VERSION 5.8 ;
BUSBITCHARS "[]" ;
DIVIDERCHAR "/" ;
UNITS
    DATABASE MICRONS 1000 ;
END UNITS

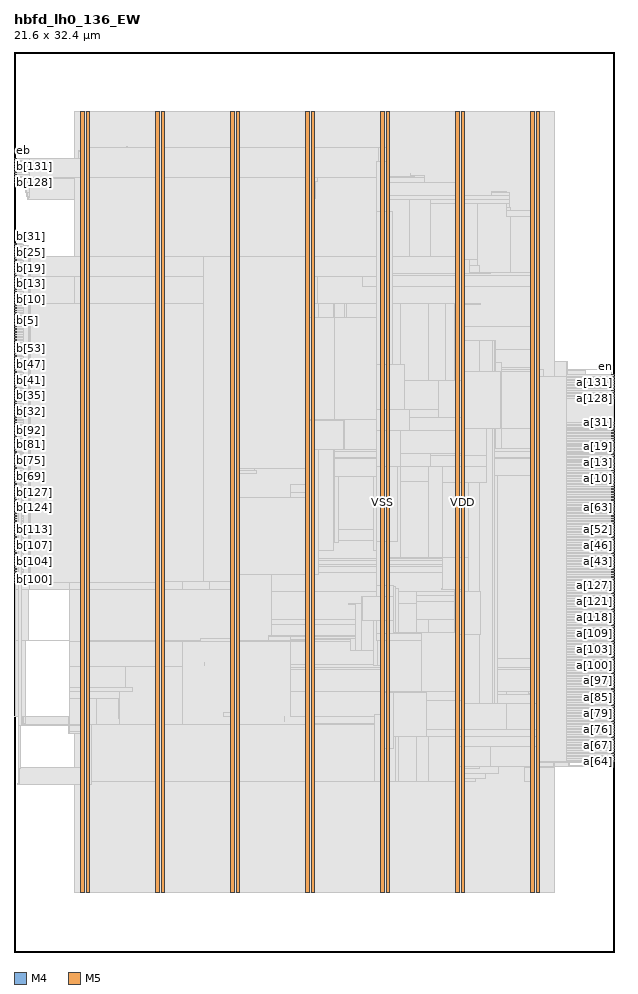
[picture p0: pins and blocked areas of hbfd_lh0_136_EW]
MACRO hbfd_lh0_136_EW
  FOREIGN hbfd_lh0_136_EW 0 0 ;
  CLASS BLOCK ;
  SIZE 21.6 BY 32.4 ;
  PIN a[0]
    DIRECTION INPUT ;
    USE SIGNAL ;
    PORT
      LAYER M4 ;
        RECT  21.516 16.08 21.6 16.104 ;
    END
  END a[0]
  PIN a[100]
    DIRECTION INPUT ;
    USE SIGNAL ;
    PORT
      LAYER M4 ;
        RECT  21.516 10.32 21.6 10.344 ;
    END
  END a[100]
  PIN a[101]
    DIRECTION INPUT ;
    USE SIGNAL ;
    PORT
      LAYER M4 ;
        RECT  21.516 10.416 21.6 10.44 ;
    END
  END a[101]
  PIN a[102]
    DIRECTION INPUT ;
    USE SIGNAL ;
    PORT
      LAYER M4 ;
        RECT  21.516 10.512 21.6 10.536 ;
    END
  END a[102]
  PIN a[103]
    DIRECTION INPUT ;
    USE SIGNAL ;
    PORT
      LAYER M4 ;
        RECT  21.516 10.608 21.6 10.632 ;
    END
  END a[103]
  PIN a[104]
    DIRECTION INPUT ;
    USE SIGNAL ;
    PORT
      LAYER M4 ;
        RECT  21.516 10.704 21.6 10.728 ;
    END
  END a[104]
  PIN a[105]
    DIRECTION INPUT ;
    USE SIGNAL ;
    PORT
      LAYER M4 ;
        RECT  21.516 10.8 21.6 10.824 ;
    END
  END a[105]
  PIN a[106]
    DIRECTION INPUT ;
    USE SIGNAL ;
    PORT
      LAYER M4 ;
        RECT  21.516 10.896 21.6 10.92 ;
    END
  END a[106]
  PIN a[107]
    DIRECTION INPUT ;
    USE SIGNAL ;
    PORT
      LAYER M4 ;
        RECT  21.516 10.992 21.6 11.016 ;
    END
  END a[107]
  PIN a[108]
    DIRECTION INPUT ;
    USE SIGNAL ;
    PORT
      LAYER M4 ;
        RECT  21.516 11.088 21.6 11.112 ;
    END
  END a[108]
  PIN a[109]
    DIRECTION INPUT ;
    USE SIGNAL ;
    PORT
      LAYER M4 ;
        RECT  21.516 11.184 21.6 11.208 ;
    END
  END a[109]
  PIN a[10]
    DIRECTION INPUT ;
    USE SIGNAL ;
    PORT
      LAYER M4 ;
        RECT  21.516 17.04 21.6 17.064 ;
    END
  END a[10]
  PIN a[110]
    DIRECTION INPUT ;
    USE SIGNAL ;
    PORT
      LAYER M4 ;
        RECT  21.516 11.28 21.6 11.304 ;
    END
  END a[110]
  PIN a[111]
    DIRECTION INPUT ;
    USE SIGNAL ;
    PORT
      LAYER M4 ;
        RECT  21.516 11.376 21.6 11.4 ;
    END
  END a[111]
  PIN a[112]
    DIRECTION INPUT ;
    USE SIGNAL ;
    PORT
      LAYER M4 ;
        RECT  21.516 11.472 21.6 11.496 ;
    END
  END a[112]
  PIN a[113]
    DIRECTION INPUT ;
    USE SIGNAL ;
    PORT
      LAYER M4 ;
        RECT  21.516 11.568 21.6 11.592 ;
    END
  END a[113]
  PIN a[114]
    DIRECTION INPUT ;
    USE SIGNAL ;
    PORT
      LAYER M4 ;
        RECT  21.516 11.664 21.6 11.688 ;
    END
  END a[114]
  PIN a[115]
    DIRECTION INPUT ;
    USE SIGNAL ;
    PORT
      LAYER M4 ;
        RECT  21.516 11.76 21.6 11.784 ;
    END
  END a[115]
  PIN a[116]
    DIRECTION INPUT ;
    USE SIGNAL ;
    PORT
      LAYER M4 ;
        RECT  21.516 11.856 21.6 11.88 ;
    END
  END a[116]
  PIN a[117]
    DIRECTION INPUT ;
    USE SIGNAL ;
    PORT
      LAYER M4 ;
        RECT  21.516 11.952 21.6 11.976 ;
    END
  END a[117]
  PIN a[118]
    DIRECTION INPUT ;
    USE SIGNAL ;
    PORT
      LAYER M4 ;
        RECT  21.516 12.048 21.6 12.072 ;
    END
  END a[118]
  PIN a[119]
    DIRECTION INPUT ;
    USE SIGNAL ;
    PORT
      LAYER M4 ;
        RECT  21.516 12.144 21.6 12.168 ;
    END
  END a[119]
  PIN a[11]
    DIRECTION INPUT ;
    USE SIGNAL ;
    PORT
      LAYER M4 ;
        RECT  21.516 17.136 21.6 17.16 ;
    END
  END a[11]
  PIN a[120]
    DIRECTION INPUT ;
    USE SIGNAL ;
    PORT
      LAYER M4 ;
        RECT  21.516 12.24 21.6 12.264 ;
    END
  END a[120]
  PIN a[121]
    DIRECTION INPUT ;
    USE SIGNAL ;
    PORT
      LAYER M4 ;
        RECT  21.516 12.336 21.6 12.36 ;
    END
  END a[121]
  PIN a[122]
    DIRECTION INPUT ;
    USE SIGNAL ;
    PORT
      LAYER M4 ;
        RECT  21.516 12.432 21.6 12.456 ;
    END
  END a[122]
  PIN a[123]
    DIRECTION INPUT ;
    USE SIGNAL ;
    PORT
      LAYER M4 ;
        RECT  21.516 12.528 21.6 12.552 ;
    END
  END a[123]
  PIN a[124]
    DIRECTION INPUT ;
    USE SIGNAL ;
    PORT
      LAYER M4 ;
        RECT  21.516 12.624 21.6 12.648 ;
    END
  END a[124]
  PIN a[125]
    DIRECTION INPUT ;
    USE SIGNAL ;
    PORT
      LAYER M4 ;
        RECT  21.516 12.72 21.6 12.744 ;
    END
  END a[125]
  PIN a[126]
    DIRECTION INPUT ;
    USE SIGNAL ;
    PORT
      LAYER M4 ;
        RECT  21.516 12.816 21.6 12.84 ;
    END
  END a[126]
  PIN a[127]
    DIRECTION INPUT ;
    USE SIGNAL ;
    PORT
      LAYER M4 ;
        RECT  21.516 12.912 21.6 12.936 ;
    END
  END a[127]
  PIN a[128]
    DIRECTION INPUT ;
    USE SIGNAL ;
    PORT
      LAYER M4 ;
        RECT  21.516 19.92 21.6 19.944 ;
    END
  END a[128]
  PIN a[129]
    DIRECTION INPUT ;
    USE SIGNAL ;
    PORT
      LAYER M4 ;
        RECT  21.516 20.016 21.6 20.04 ;
    END
  END a[129]
  PIN a[12]
    DIRECTION INPUT ;
    USE SIGNAL ;
    PORT
      LAYER M4 ;
        RECT  21.516 17.232 21.6 17.256 ;
    END
  END a[12]
  PIN a[130]
    DIRECTION INPUT ;
    USE SIGNAL ;
    PORT
      LAYER M4 ;
        RECT  21.516 20.112 21.6 20.136 ;
    END
  END a[130]
  PIN a[131]
    DIRECTION INPUT ;
    USE SIGNAL ;
    PORT
      LAYER M4 ;
        RECT  21.516 20.208 21.6 20.232 ;
    END
  END a[131]
  PIN a[132]
    DIRECTION INPUT ;
    USE SIGNAL ;
    PORT
      LAYER M4 ;
        RECT  21.516 20.304 21.6 20.328 ;
    END
  END a[132]
  PIN a[133]
    DIRECTION INPUT ;
    USE SIGNAL ;
    PORT
      LAYER M4 ;
        RECT  21.516 20.4 21.6 20.424 ;
    END
  END a[133]
  PIN a[134]
    DIRECTION INPUT ;
    USE SIGNAL ;
    PORT
      LAYER M4 ;
        RECT  21.516 20.496 21.6 20.52 ;
    END
  END a[134]
  PIN a[135]
    DIRECTION INPUT ;
    USE SIGNAL ;
    PORT
      LAYER M4 ;
        RECT  21.516 20.592 21.6 20.616 ;
    END
  END a[135]
  PIN a[13]
    DIRECTION INPUT ;
    USE SIGNAL ;
    PORT
      LAYER M4 ;
        RECT  21.516 17.328 21.6 17.352 ;
    END
  END a[13]
  PIN a[14]
    DIRECTION INPUT ;
    USE SIGNAL ;
    PORT
      LAYER M4 ;
        RECT  21.516 17.424 21.6 17.448 ;
    END
  END a[14]
  PIN a[15]
    DIRECTION INPUT ;
    USE SIGNAL ;
    PORT
      LAYER M4 ;
        RECT  21.516 17.52 21.6 17.544 ;
    END
  END a[15]
  PIN a[16]
    DIRECTION INPUT ;
    USE SIGNAL ;
    PORT
      LAYER M4 ;
        RECT  21.516 17.616 21.6 17.64 ;
    END
  END a[16]
  PIN a[17]
    DIRECTION INPUT ;
    USE SIGNAL ;
    PORT
      LAYER M4 ;
        RECT  21.516 17.712 21.6 17.736 ;
    END
  END a[17]
  PIN a[18]
    DIRECTION INPUT ;
    USE SIGNAL ;
    PORT
      LAYER M4 ;
        RECT  21.516 17.808 21.6 17.832 ;
    END
  END a[18]
  PIN a[19]
    DIRECTION INPUT ;
    USE SIGNAL ;
    PORT
      LAYER M4 ;
        RECT  21.516 17.904 21.6 17.928 ;
    END
  END a[19]
  PIN a[1]
    DIRECTION INPUT ;
    USE SIGNAL ;
    PORT
      LAYER M4 ;
        RECT  21.516 16.176 21.6 16.2 ;
    END
  END a[1]
  PIN a[20]
    DIRECTION INPUT ;
    USE SIGNAL ;
    PORT
      LAYER M4 ;
        RECT  21.516 18 21.6 18.024 ;
    END
  END a[20]
  PIN a[21]
    DIRECTION INPUT ;
    USE SIGNAL ;
    PORT
      LAYER M4 ;
        RECT  21.516 18.096 21.6 18.12 ;
    END
  END a[21]
  PIN a[22]
    DIRECTION INPUT ;
    USE SIGNAL ;
    PORT
      LAYER M4 ;
        RECT  21.516 18.192 21.6 18.216 ;
    END
  END a[22]
  PIN a[23]
    DIRECTION INPUT ;
    USE SIGNAL ;
    PORT
      LAYER M4 ;
        RECT  21.516 18.288 21.6 18.312 ;
    END
  END a[23]
  PIN a[24]
    DIRECTION INPUT ;
    USE SIGNAL ;
    PORT
      LAYER M4 ;
        RECT  21.516 18.384 21.6 18.408 ;
    END
  END a[24]
  PIN a[25]
    DIRECTION INPUT ;
    USE SIGNAL ;
    PORT
      LAYER M4 ;
        RECT  21.516 18.48 21.6 18.504 ;
    END
  END a[25]
  PIN a[26]
    DIRECTION INPUT ;
    USE SIGNAL ;
    PORT
      LAYER M4 ;
        RECT  21.516 18.576 21.6 18.6 ;
    END
  END a[26]
  PIN a[27]
    DIRECTION INPUT ;
    USE SIGNAL ;
    PORT
      LAYER M4 ;
        RECT  21.516 18.672 21.6 18.696 ;
    END
  END a[27]
  PIN a[28]
    DIRECTION INPUT ;
    USE SIGNAL ;
    PORT
      LAYER M4 ;
        RECT  21.516 18.768 21.6 18.792 ;
    END
  END a[28]
  PIN a[29]
    DIRECTION INPUT ;
    USE SIGNAL ;
    PORT
      LAYER M4 ;
        RECT  21.516 18.864 21.6 18.888 ;
    END
  END a[29]
  PIN a[2]
    DIRECTION INPUT ;
    USE SIGNAL ;
    PORT
      LAYER M4 ;
        RECT  21.516 16.272 21.6 16.296 ;
    END
  END a[2]
  PIN a[30]
    DIRECTION INPUT ;
    USE SIGNAL ;
    PORT
      LAYER M4 ;
        RECT  21.516 18.96 21.6 18.984 ;
    END
  END a[30]
  PIN a[31]
    DIRECTION INPUT ;
    USE SIGNAL ;
    PORT
      LAYER M4 ;
        RECT  21.516 19.056 21.6 19.08 ;
    END
  END a[31]
  PIN a[32]
    DIRECTION INPUT ;
    USE SIGNAL ;
    PORT
      LAYER M4 ;
        RECT  21.516 13.008 21.6 13.032 ;
    END
  END a[32]
  PIN a[33]
    DIRECTION INPUT ;
    USE SIGNAL ;
    PORT
      LAYER M4 ;
        RECT  21.516 13.104 21.6 13.128 ;
    END
  END a[33]
  PIN a[34]
    DIRECTION INPUT ;
    USE SIGNAL ;
    PORT
      LAYER M4 ;
        RECT  21.516 13.2 21.6 13.224 ;
    END
  END a[34]
  PIN a[35]
    DIRECTION INPUT ;
    USE SIGNAL ;
    PORT
      LAYER M4 ;
        RECT  21.516 13.296 21.6 13.32 ;
    END
  END a[35]
  PIN a[36]
    DIRECTION INPUT ;
    USE SIGNAL ;
    PORT
      LAYER M4 ;
        RECT  21.516 13.392 21.6 13.416 ;
    END
  END a[36]
  PIN a[37]
    DIRECTION INPUT ;
    USE SIGNAL ;
    PORT
      LAYER M4 ;
        RECT  21.516 13.488 21.6 13.512 ;
    END
  END a[37]
  PIN a[38]
    DIRECTION INPUT ;
    USE SIGNAL ;
    PORT
      LAYER M4 ;
        RECT  21.516 13.584 21.6 13.608 ;
    END
  END a[38]
  PIN a[39]
    DIRECTION INPUT ;
    USE SIGNAL ;
    PORT
      LAYER M4 ;
        RECT  21.516 13.68 21.6 13.704 ;
    END
  END a[39]
  PIN a[3]
    DIRECTION INPUT ;
    USE SIGNAL ;
    PORT
      LAYER M4 ;
        RECT  21.516 16.368 21.6 16.392 ;
    END
  END a[3]
  PIN a[40]
    DIRECTION INPUT ;
    USE SIGNAL ;
    PORT
      LAYER M4 ;
        RECT  21.516 13.776 21.6 13.8 ;
    END
  END a[40]
  PIN a[41]
    DIRECTION INPUT ;
    USE SIGNAL ;
    PORT
      LAYER M4 ;
        RECT  21.516 13.872 21.6 13.896 ;
    END
  END a[41]
  PIN a[42]
    DIRECTION INPUT ;
    USE SIGNAL ;
    PORT
      LAYER M4 ;
        RECT  21.516 13.968 21.6 13.992 ;
    END
  END a[42]
  PIN a[43]
    DIRECTION INPUT ;
    USE SIGNAL ;
    PORT
      LAYER M4 ;
        RECT  21.516 14.064 21.6 14.088 ;
    END
  END a[43]
  PIN a[44]
    DIRECTION INPUT ;
    USE SIGNAL ;
    PORT
      LAYER M4 ;
        RECT  21.516 14.16 21.6 14.184 ;
    END
  END a[44]
  PIN a[45]
    DIRECTION INPUT ;
    USE SIGNAL ;
    PORT
      LAYER M4 ;
        RECT  21.516 14.256 21.6 14.28 ;
    END
  END a[45]
  PIN a[46]
    DIRECTION INPUT ;
    USE SIGNAL ;
    PORT
      LAYER M4 ;
        RECT  21.516 14.352 21.6 14.376 ;
    END
  END a[46]
  PIN a[47]
    DIRECTION INPUT ;
    USE SIGNAL ;
    PORT
      LAYER M4 ;
        RECT  21.516 14.448 21.6 14.472 ;
    END
  END a[47]
  PIN a[48]
    DIRECTION INPUT ;
    USE SIGNAL ;
    PORT
      LAYER M4 ;
        RECT  21.516 14.544 21.6 14.568 ;
    END
  END a[48]
  PIN a[49]
    DIRECTION INPUT ;
    USE SIGNAL ;
    PORT
      LAYER M4 ;
        RECT  21.516 14.64 21.6 14.664 ;
    END
  END a[49]
  PIN a[4]
    DIRECTION INPUT ;
    USE SIGNAL ;
    PORT
      LAYER M4 ;
        RECT  21.516 16.464 21.6 16.488 ;
    END
  END a[4]
  PIN a[50]
    DIRECTION INPUT ;
    USE SIGNAL ;
    PORT
      LAYER M4 ;
        RECT  21.516 14.736 21.6 14.76 ;
    END
  END a[50]
  PIN a[51]
    DIRECTION INPUT ;
    USE SIGNAL ;
    PORT
      LAYER M4 ;
        RECT  21.516 14.832 21.6 14.856 ;
    END
  END a[51]
  PIN a[52]
    DIRECTION INPUT ;
    USE SIGNAL ;
    PORT
      LAYER M4 ;
        RECT  21.516 14.928 21.6 14.952 ;
    END
  END a[52]
  PIN a[53]
    DIRECTION INPUT ;
    USE SIGNAL ;
    PORT
      LAYER M4 ;
        RECT  21.516 15.024 21.6 15.048 ;
    END
  END a[53]
  PIN a[54]
    DIRECTION INPUT ;
    USE SIGNAL ;
    PORT
      LAYER M4 ;
        RECT  21.516 15.12 21.6 15.144 ;
    END
  END a[54]
  PIN a[55]
    DIRECTION INPUT ;
    USE SIGNAL ;
    PORT
      LAYER M4 ;
        RECT  21.516 15.216 21.6 15.24 ;
    END
  END a[55]
  PIN a[56]
    DIRECTION INPUT ;
    USE SIGNAL ;
    PORT
      LAYER M4 ;
        RECT  21.516 15.312 21.6 15.336 ;
    END
  END a[56]
  PIN a[57]
    DIRECTION INPUT ;
    USE SIGNAL ;
    PORT
      LAYER M4 ;
        RECT  21.516 15.408 21.6 15.432 ;
    END
  END a[57]
  PIN a[58]
    DIRECTION INPUT ;
    USE SIGNAL ;
    PORT
      LAYER M4 ;
        RECT  21.516 15.504 21.6 15.528 ;
    END
  END a[58]
  PIN a[59]
    DIRECTION INPUT ;
    USE SIGNAL ;
    PORT
      LAYER M4 ;
        RECT  21.516 15.6 21.6 15.624 ;
    END
  END a[59]
  PIN a[5]
    DIRECTION INPUT ;
    USE SIGNAL ;
    PORT
      LAYER M4 ;
        RECT  21.516 16.56 21.6 16.584 ;
    END
  END a[5]
  PIN a[60]
    DIRECTION INPUT ;
    USE SIGNAL ;
    PORT
      LAYER M4 ;
        RECT  21.516 15.696 21.6 15.72 ;
    END
  END a[60]
  PIN a[61]
    DIRECTION INPUT ;
    USE SIGNAL ;
    PORT
      LAYER M4 ;
        RECT  21.516 15.792 21.6 15.816 ;
    END
  END a[61]
  PIN a[62]
    DIRECTION INPUT ;
    USE SIGNAL ;
    PORT
      LAYER M4 ;
        RECT  21.516 15.888 21.6 15.912 ;
    END
  END a[62]
  PIN a[63]
    DIRECTION INPUT ;
    USE SIGNAL ;
    PORT
      LAYER M4 ;
        RECT  21.516 15.984 21.6 16.008 ;
    END
  END a[63]
  PIN a[64]
    DIRECTION INPUT ;
    USE SIGNAL ;
    PORT
      LAYER M4 ;
        RECT  21.516 6.864 21.6 6.888 ;
    END
  END a[64]
  PIN a[65]
    DIRECTION INPUT ;
    USE SIGNAL ;
    PORT
      LAYER M4 ;
        RECT  21.516 6.96 21.6 6.984 ;
    END
  END a[65]
  PIN a[66]
    DIRECTION INPUT ;
    USE SIGNAL ;
    PORT
      LAYER M4 ;
        RECT  21.516 7.056 21.6 7.08 ;
    END
  END a[66]
  PIN a[67]
    DIRECTION INPUT ;
    USE SIGNAL ;
    PORT
      LAYER M4 ;
        RECT  21.516 7.152 21.6 7.176 ;
    END
  END a[67]
  PIN a[68]
    DIRECTION INPUT ;
    USE SIGNAL ;
    PORT
      LAYER M4 ;
        RECT  21.516 7.248 21.6 7.272 ;
    END
  END a[68]
  PIN a[69]
    DIRECTION INPUT ;
    USE SIGNAL ;
    PORT
      LAYER M4 ;
        RECT  21.516 7.344 21.6 7.368 ;
    END
  END a[69]
  PIN a[6]
    DIRECTION INPUT ;
    USE SIGNAL ;
    PORT
      LAYER M4 ;
        RECT  21.516 16.656 21.6 16.68 ;
    END
  END a[6]
  PIN a[70]
    DIRECTION INPUT ;
    USE SIGNAL ;
    PORT
      LAYER M4 ;
        RECT  21.516 7.44 21.6 7.464 ;
    END
  END a[70]
  PIN a[71]
    DIRECTION INPUT ;
    USE SIGNAL ;
    PORT
      LAYER M4 ;
        RECT  21.516 7.536 21.6 7.56 ;
    END
  END a[71]
  PIN a[72]
    DIRECTION INPUT ;
    USE SIGNAL ;
    PORT
      LAYER M4 ;
        RECT  21.516 7.632 21.6 7.656 ;
    END
  END a[72]
  PIN a[73]
    DIRECTION INPUT ;
    USE SIGNAL ;
    PORT
      LAYER M4 ;
        RECT  21.516 7.728 21.6 7.752 ;
    END
  END a[73]
  PIN a[74]
    DIRECTION INPUT ;
    USE SIGNAL ;
    PORT
      LAYER M4 ;
        RECT  21.516 7.824 21.6 7.848 ;
    END
  END a[74]
  PIN a[75]
    DIRECTION INPUT ;
    USE SIGNAL ;
    PORT
      LAYER M4 ;
        RECT  21.516 7.92 21.6 7.944 ;
    END
  END a[75]
  PIN a[76]
    DIRECTION INPUT ;
    USE SIGNAL ;
    PORT
      LAYER M4 ;
        RECT  21.516 8.016 21.6 8.04 ;
    END
  END a[76]
  PIN a[77]
    DIRECTION INPUT ;
    USE SIGNAL ;
    PORT
      LAYER M4 ;
        RECT  21.516 8.112 21.6 8.136 ;
    END
  END a[77]
  PIN a[78]
    DIRECTION INPUT ;
    USE SIGNAL ;
    PORT
      LAYER M4 ;
        RECT  21.516 8.208 21.6 8.232 ;
    END
  END a[78]
  PIN a[79]
    DIRECTION INPUT ;
    USE SIGNAL ;
    PORT
      LAYER M4 ;
        RECT  21.516 8.304 21.6 8.328 ;
    END
  END a[79]
  PIN a[7]
    DIRECTION INPUT ;
    USE SIGNAL ;
    PORT
      LAYER M4 ;
        RECT  21.516 16.752 21.6 16.776 ;
    END
  END a[7]
  PIN a[80]
    DIRECTION INPUT ;
    USE SIGNAL ;
    PORT
      LAYER M4 ;
        RECT  21.516 8.4 21.6 8.424 ;
    END
  END a[80]
  PIN a[81]
    DIRECTION INPUT ;
    USE SIGNAL ;
    PORT
      LAYER M4 ;
        RECT  21.516 8.496 21.6 8.52 ;
    END
  END a[81]
  PIN a[82]
    DIRECTION INPUT ;
    USE SIGNAL ;
    PORT
      LAYER M4 ;
        RECT  21.516 8.592 21.6 8.616 ;
    END
  END a[82]
  PIN a[83]
    DIRECTION INPUT ;
    USE SIGNAL ;
    PORT
      LAYER M4 ;
        RECT  21.516 8.688 21.6 8.712 ;
    END
  END a[83]
  PIN a[84]
    DIRECTION INPUT ;
    USE SIGNAL ;
    PORT
      LAYER M4 ;
        RECT  21.516 8.784 21.6 8.808 ;
    END
  END a[84]
  PIN a[85]
    DIRECTION INPUT ;
    USE SIGNAL ;
    PORT
      LAYER M4 ;
        RECT  21.516 8.88 21.6 8.904 ;
    END
  END a[85]
  PIN a[86]
    DIRECTION INPUT ;
    USE SIGNAL ;
    PORT
      LAYER M4 ;
        RECT  21.516 8.976 21.6 9 ;
    END
  END a[86]
  PIN a[87]
    DIRECTION INPUT ;
    USE SIGNAL ;
    PORT
      LAYER M4 ;
        RECT  21.516 9.072 21.6 9.096 ;
    END
  END a[87]
  PIN a[88]
    DIRECTION INPUT ;
    USE SIGNAL ;
    PORT
      LAYER M4 ;
        RECT  21.516 9.168 21.6 9.192 ;
    END
  END a[88]
  PIN a[89]
    DIRECTION INPUT ;
    USE SIGNAL ;
    PORT
      LAYER M4 ;
        RECT  21.516 9.264 21.6 9.288 ;
    END
  END a[89]
  PIN a[8]
    DIRECTION INPUT ;
    USE SIGNAL ;
    PORT
      LAYER M4 ;
        RECT  21.516 16.848 21.6 16.872 ;
    END
  END a[8]
  PIN a[90]
    DIRECTION INPUT ;
    USE SIGNAL ;
    PORT
      LAYER M4 ;
        RECT  21.516 9.36 21.6 9.384 ;
    END
  END a[90]
  PIN a[91]
    DIRECTION INPUT ;
    USE SIGNAL ;
    PORT
      LAYER M4 ;
        RECT  21.516 9.456 21.6 9.48 ;
    END
  END a[91]
  PIN a[92]
    DIRECTION INPUT ;
    USE SIGNAL ;
    PORT
      LAYER M4 ;
        RECT  21.516 9.552 21.6 9.576 ;
    END
  END a[92]
  PIN a[93]
    DIRECTION INPUT ;
    USE SIGNAL ;
    PORT
      LAYER M4 ;
        RECT  21.516 9.648 21.6 9.672 ;
    END
  END a[93]
  PIN a[94]
    DIRECTION INPUT ;
    USE SIGNAL ;
    PORT
      LAYER M4 ;
        RECT  21.516 9.744 21.6 9.768 ;
    END
  END a[94]
  PIN a[95]
    DIRECTION INPUT ;
    USE SIGNAL ;
    PORT
      LAYER M4 ;
        RECT  21.516 9.84 21.6 9.864 ;
    END
  END a[95]
  PIN a[96]
    DIRECTION INPUT ;
    USE SIGNAL ;
    PORT
      LAYER M4 ;
        RECT  21.516 9.936 21.6 9.96 ;
    END
  END a[96]
  PIN a[97]
    DIRECTION INPUT ;
    USE SIGNAL ;
    PORT
      LAYER M4 ;
        RECT  21.516 10.032 21.6 10.056 ;
    END
  END a[97]
  PIN a[98]
    DIRECTION INPUT ;
    USE SIGNAL ;
    PORT
      LAYER M4 ;
        RECT  21.516 10.128 21.6 10.152 ;
    END
  END a[98]
  PIN a[99]
    DIRECTION INPUT ;
    USE SIGNAL ;
    PORT
      LAYER M4 ;
        RECT  21.516 10.224 21.6 10.248 ;
    END
  END a[99]
  PIN a[9]
    DIRECTION INPUT ;
    USE SIGNAL ;
    PORT
      LAYER M4 ;
        RECT  21.516 16.944 21.6 16.968 ;
    END
  END a[9]
  PIN b[0]
    DIRECTION OUTPUT ;
    USE SIGNAL ;
    PORT
      LAYER M4 ;
        RECT  0 22.512 0.084 22.536 ;
    END
  END b[0]
  PIN b[100]
    DIRECTION OUTPUT ;
    USE SIGNAL ;
    PORT
      LAYER M4 ;
        RECT  0 13.68 0.084 13.704 ;
    END
  END b[100]
  PIN b[101]
    DIRECTION OUTPUT ;
    USE SIGNAL ;
    PORT
      LAYER M4 ;
        RECT  0 13.776 0.084 13.8 ;
    END
  END b[101]
  PIN b[102]
    DIRECTION OUTPUT ;
    USE SIGNAL ;
    PORT
      LAYER M4 ;
        RECT  0 13.872 0.084 13.896 ;
    END
  END b[102]
  PIN b[103]
    DIRECTION OUTPUT ;
    USE SIGNAL ;
    PORT
      LAYER M4 ;
        RECT  0 13.968 0.084 13.992 ;
    END
  END b[103]
  PIN b[104]
    DIRECTION OUTPUT ;
    USE SIGNAL ;
    PORT
      LAYER M4 ;
        RECT  0 14.064 0.084 14.088 ;
    END
  END b[104]
  PIN b[105]
    DIRECTION OUTPUT ;
    USE SIGNAL ;
    PORT
      LAYER M4 ;
        RECT  0 14.16 0.084 14.184 ;
    END
  END b[105]
  PIN b[106]
    DIRECTION OUTPUT ;
    USE SIGNAL ;
    PORT
      LAYER M4 ;
        RECT  0 14.256 0.084 14.28 ;
    END
  END b[106]
  PIN b[107]
    DIRECTION OUTPUT ;
    USE SIGNAL ;
    PORT
      LAYER M4 ;
        RECT  0 14.352 0.084 14.376 ;
    END
  END b[107]
  PIN b[108]
    DIRECTION OUTPUT ;
    USE SIGNAL ;
    PORT
      LAYER M4 ;
        RECT  0 14.448 0.084 14.472 ;
    END
  END b[108]
  PIN b[109]
    DIRECTION OUTPUT ;
    USE SIGNAL ;
    PORT
      LAYER M4 ;
        RECT  0 14.544 0.084 14.568 ;
    END
  END b[109]
  PIN b[10]
    DIRECTION OUTPUT ;
    USE SIGNAL ;
    PORT
      LAYER M4 ;
        RECT  0 23.472 0.084 23.496 ;
    END
  END b[10]
  PIN b[110]
    DIRECTION OUTPUT ;
    USE SIGNAL ;
    PORT
      LAYER M4 ;
        RECT  0 14.64 0.084 14.664 ;
    END
  END b[110]
  PIN b[111]
    DIRECTION OUTPUT ;
    USE SIGNAL ;
    PORT
      LAYER M4 ;
        RECT  0 14.736 0.084 14.76 ;
    END
  END b[111]
  PIN b[112]
    DIRECTION OUTPUT ;
    USE SIGNAL ;
    PORT
      LAYER M4 ;
        RECT  0 14.832 0.084 14.856 ;
    END
  END b[112]
  PIN b[113]
    DIRECTION OUTPUT ;
    USE SIGNAL ;
    PORT
      LAYER M4 ;
        RECT  0 14.928 0.084 14.952 ;
    END
  END b[113]
  PIN b[114]
    DIRECTION OUTPUT ;
    USE SIGNAL ;
    PORT
      LAYER M4 ;
        RECT  0 15.024 0.084 15.048 ;
    END
  END b[114]
  PIN b[115]
    DIRECTION OUTPUT ;
    USE SIGNAL ;
    PORT
      LAYER M4 ;
        RECT  0 15.12 0.084 15.144 ;
    END
  END b[115]
  PIN b[116]
    DIRECTION OUTPUT ;
    USE SIGNAL ;
    PORT
      LAYER M4 ;
        RECT  0 15.216 0.084 15.24 ;
    END
  END b[116]
  PIN b[117]
    DIRECTION OUTPUT ;
    USE SIGNAL ;
    PORT
      LAYER M4 ;
        RECT  0 15.312 0.084 15.336 ;
    END
  END b[117]
  PIN b[118]
    DIRECTION OUTPUT ;
    USE SIGNAL ;
    PORT
      LAYER M4 ;
        RECT  0 15.408 0.084 15.432 ;
    END
  END b[118]
  PIN b[119]
    DIRECTION OUTPUT ;
    USE SIGNAL ;
    PORT
      LAYER M4 ;
        RECT  0 15.504 0.084 15.528 ;
    END
  END b[119]
  PIN b[11]
    DIRECTION OUTPUT ;
    USE SIGNAL ;
    PORT
      LAYER M4 ;
        RECT  0 23.568 0.084 23.592 ;
    END
  END b[11]
  PIN b[120]
    DIRECTION OUTPUT ;
    USE SIGNAL ;
    PORT
      LAYER M4 ;
        RECT  0 15.6 0.084 15.624 ;
    END
  END b[120]
  PIN b[121]
    DIRECTION OUTPUT ;
    USE SIGNAL ;
    PORT
      LAYER M4 ;
        RECT  0 15.696 0.084 15.72 ;
    END
  END b[121]
  PIN b[122]
    DIRECTION OUTPUT ;
    USE SIGNAL ;
    PORT
      LAYER M4 ;
        RECT  0 15.792 0.084 15.816 ;
    END
  END b[122]
  PIN b[123]
    DIRECTION OUTPUT ;
    USE SIGNAL ;
    PORT
      LAYER M4 ;
        RECT  0 15.888 0.084 15.912 ;
    END
  END b[123]
  PIN b[124]
    DIRECTION OUTPUT ;
    USE SIGNAL ;
    PORT
      LAYER M4 ;
        RECT  0 15.984 0.084 16.008 ;
    END
  END b[124]
  PIN b[125]
    DIRECTION OUTPUT ;
    USE SIGNAL ;
    PORT
      LAYER M4 ;
        RECT  0 16.08 0.084 16.104 ;
    END
  END b[125]
  PIN b[126]
    DIRECTION OUTPUT ;
    USE SIGNAL ;
    PORT
      LAYER M4 ;
        RECT  0 16.176 0.084 16.2 ;
    END
  END b[126]
  PIN b[127]
    DIRECTION OUTPUT ;
    USE SIGNAL ;
    PORT
      LAYER M4 ;
        RECT  0 16.272 0.084 16.296 ;
    END
  END b[127]
  PIN b[128]
    DIRECTION OUTPUT ;
    USE SIGNAL ;
    PORT
      LAYER M4 ;
        RECT  0 27.696 0.084 27.72 ;
    END
  END b[128]
  PIN b[129]
    DIRECTION OUTPUT ;
    USE SIGNAL ;
    PORT
      LAYER M4 ;
        RECT  0 27.792 0.084 27.816 ;
    END
  END b[129]
  PIN b[12]
    DIRECTION OUTPUT ;
    USE SIGNAL ;
    PORT
      LAYER M4 ;
        RECT  0 23.664 0.084 23.688 ;
    END
  END b[12]
  PIN b[130]
    DIRECTION OUTPUT ;
    USE SIGNAL ;
    PORT
      LAYER M4 ;
        RECT  0 27.888 0.084 27.912 ;
    END
  END b[130]
  PIN b[131]
    DIRECTION OUTPUT ;
    USE SIGNAL ;
    PORT
      LAYER M4 ;
        RECT  0 27.984 0.084 28.008 ;
    END
  END b[131]
  PIN b[132]
    DIRECTION OUTPUT ;
    USE SIGNAL ;
    PORT
      LAYER M4 ;
        RECT  0 28.08 0.084 28.104 ;
    END
  END b[132]
  PIN b[133]
    DIRECTION OUTPUT ;
    USE SIGNAL ;
    PORT
      LAYER M4 ;
        RECT  0 28.176 0.084 28.2 ;
    END
  END b[133]
  PIN b[134]
    DIRECTION OUTPUT ;
    USE SIGNAL ;
    PORT
      LAYER M4 ;
        RECT  0 28.272 0.084 28.296 ;
    END
  END b[134]
  PIN b[135]
    DIRECTION OUTPUT ;
    USE SIGNAL ;
    PORT
      LAYER M4 ;
        RECT  0 28.368 0.084 28.392 ;
    END
  END b[135]
  PIN b[13]
    DIRECTION OUTPUT ;
    USE SIGNAL ;
    PORT
      LAYER M4 ;
        RECT  0 23.76 0.084 23.784 ;
    END
  END b[13]
  PIN b[14]
    DIRECTION OUTPUT ;
    USE SIGNAL ;
    PORT
      LAYER M4 ;
        RECT  0 23.856 0.084 23.88 ;
    END
  END b[14]
  PIN b[15]
    DIRECTION OUTPUT ;
    USE SIGNAL ;
    PORT
      LAYER M4 ;
        RECT  0 23.952 0.084 23.976 ;
    END
  END b[15]
  PIN b[16]
    DIRECTION OUTPUT ;
    USE SIGNAL ;
    PORT
      LAYER M4 ;
        RECT  0 24.048 0.084 24.072 ;
    END
  END b[16]
  PIN b[17]
    DIRECTION OUTPUT ;
    USE SIGNAL ;
    PORT
      LAYER M4 ;
        RECT  0 24.144 0.084 24.168 ;
    END
  END b[17]
  PIN b[18]
    DIRECTION OUTPUT ;
    USE SIGNAL ;
    PORT
      LAYER M4 ;
        RECT  0 24.24 0.084 24.264 ;
    END
  END b[18]
  PIN b[19]
    DIRECTION OUTPUT ;
    USE SIGNAL ;
    PORT
      LAYER M4 ;
        RECT  0 24.336 0.084 24.36 ;
    END
  END b[19]
  PIN b[1]
    DIRECTION OUTPUT ;
    USE SIGNAL ;
    PORT
      LAYER M4 ;
        RECT  0 22.608 0.084 22.632 ;
    END
  END b[1]
  PIN b[20]
    DIRECTION OUTPUT ;
    USE SIGNAL ;
    PORT
      LAYER M4 ;
        RECT  0 24.432 0.084 24.456 ;
    END
  END b[20]
  PIN b[21]
    DIRECTION OUTPUT ;
    USE SIGNAL ;
    PORT
      LAYER M4 ;
        RECT  0 24.528 0.084 24.552 ;
    END
  END b[21]
  PIN b[22]
    DIRECTION OUTPUT ;
    USE SIGNAL ;
    PORT
      LAYER M4 ;
        RECT  0 24.624 0.084 24.648 ;
    END
  END b[22]
  PIN b[23]
    DIRECTION OUTPUT ;
    USE SIGNAL ;
    PORT
      LAYER M4 ;
        RECT  0 24.72 0.084 24.744 ;
    END
  END b[23]
  PIN b[24]
    DIRECTION OUTPUT ;
    USE SIGNAL ;
    PORT
      LAYER M4 ;
        RECT  0 24.816 0.084 24.84 ;
    END
  END b[24]
  PIN b[25]
    DIRECTION OUTPUT ;
    USE SIGNAL ;
    PORT
      LAYER M4 ;
        RECT  0 24.912 0.084 24.936 ;
    END
  END b[25]
  PIN b[26]
    DIRECTION OUTPUT ;
    USE SIGNAL ;
    PORT
      LAYER M4 ;
        RECT  0 25.008 0.084 25.032 ;
    END
  END b[26]
  PIN b[27]
    DIRECTION OUTPUT ;
    USE SIGNAL ;
    PORT
      LAYER M4 ;
        RECT  0 25.104 0.084 25.128 ;
    END
  END b[27]
  PIN b[28]
    DIRECTION OUTPUT ;
    USE SIGNAL ;
    PORT
      LAYER M4 ;
        RECT  0 25.2 0.084 25.224 ;
    END
  END b[28]
  PIN b[29]
    DIRECTION OUTPUT ;
    USE SIGNAL ;
    PORT
      LAYER M4 ;
        RECT  0 25.296 0.084 25.32 ;
    END
  END b[29]
  PIN b[2]
    DIRECTION OUTPUT ;
    USE SIGNAL ;
    PORT
      LAYER M4 ;
        RECT  0 22.704 0.084 22.728 ;
    END
  END b[2]
  PIN b[30]
    DIRECTION OUTPUT ;
    USE SIGNAL ;
    PORT
      LAYER M4 ;
        RECT  0 25.392 0.084 25.416 ;
    END
  END b[30]
  PIN b[31]
    DIRECTION OUTPUT ;
    USE SIGNAL ;
    PORT
      LAYER M4 ;
        RECT  0 25.488 0.084 25.512 ;
    END
  END b[31]
  PIN b[32]
    DIRECTION OUTPUT ;
    USE SIGNAL ;
    PORT
      LAYER M4 ;
        RECT  0 19.44 0.084 19.464 ;
    END
  END b[32]
  PIN b[33]
    DIRECTION OUTPUT ;
    USE SIGNAL ;
    PORT
      LAYER M4 ;
        RECT  0 19.536 0.084 19.56 ;
    END
  END b[33]
  PIN b[34]
    DIRECTION OUTPUT ;
    USE SIGNAL ;
    PORT
      LAYER M4 ;
        RECT  0 19.632 0.084 19.656 ;
    END
  END b[34]
  PIN b[35]
    DIRECTION OUTPUT ;
    USE SIGNAL ;
    PORT
      LAYER M4 ;
        RECT  0 19.728 0.084 19.752 ;
    END
  END b[35]
  PIN b[36]
    DIRECTION OUTPUT ;
    USE SIGNAL ;
    PORT
      LAYER M4 ;
        RECT  0 19.824 0.084 19.848 ;
    END
  END b[36]
  PIN b[37]
    DIRECTION OUTPUT ;
    USE SIGNAL ;
    PORT
      LAYER M4 ;
        RECT  0 19.92 0.084 19.944 ;
    END
  END b[37]
  PIN b[38]
    DIRECTION OUTPUT ;
    USE SIGNAL ;
    PORT
      LAYER M4 ;
        RECT  0 20.016 0.084 20.04 ;
    END
  END b[38]
  PIN b[39]
    DIRECTION OUTPUT ;
    USE SIGNAL ;
    PORT
      LAYER M4 ;
        RECT  0 20.112 0.084 20.136 ;
    END
  END b[39]
  PIN b[3]
    DIRECTION OUTPUT ;
    USE SIGNAL ;
    PORT
      LAYER M4 ;
        RECT  0 22.8 0.084 22.824 ;
    END
  END b[3]
  PIN b[40]
    DIRECTION OUTPUT ;
    USE SIGNAL ;
    PORT
      LAYER M4 ;
        RECT  0 20.208 0.084 20.232 ;
    END
  END b[40]
  PIN b[41]
    DIRECTION OUTPUT ;
    USE SIGNAL ;
    PORT
      LAYER M4 ;
        RECT  0 20.304 0.084 20.328 ;
    END
  END b[41]
  PIN b[42]
    DIRECTION OUTPUT ;
    USE SIGNAL ;
    PORT
      LAYER M4 ;
        RECT  0 20.4 0.084 20.424 ;
    END
  END b[42]
  PIN b[43]
    DIRECTION OUTPUT ;
    USE SIGNAL ;
    PORT
      LAYER M4 ;
        RECT  0 20.496 0.084 20.52 ;
    END
  END b[43]
  PIN b[44]
    DIRECTION OUTPUT ;
    USE SIGNAL ;
    PORT
      LAYER M4 ;
        RECT  0 20.592 0.084 20.616 ;
    END
  END b[44]
  PIN b[45]
    DIRECTION OUTPUT ;
    USE SIGNAL ;
    PORT
      LAYER M4 ;
        RECT  0 20.688 0.084 20.712 ;
    END
  END b[45]
  PIN b[46]
    DIRECTION OUTPUT ;
    USE SIGNAL ;
    PORT
      LAYER M4 ;
        RECT  0 20.784 0.084 20.808 ;
    END
  END b[46]
  PIN b[47]
    DIRECTION OUTPUT ;
    USE SIGNAL ;
    PORT
      LAYER M4 ;
        RECT  0 20.88 0.084 20.904 ;
    END
  END b[47]
  PIN b[48]
    DIRECTION OUTPUT ;
    USE SIGNAL ;
    PORT
      LAYER M4 ;
        RECT  0 20.976 0.084 21 ;
    END
  END b[48]
  PIN b[49]
    DIRECTION OUTPUT ;
    USE SIGNAL ;
    PORT
      LAYER M4 ;
        RECT  0 21.072 0.084 21.096 ;
    END
  END b[49]
  PIN b[4]
    DIRECTION OUTPUT ;
    USE SIGNAL ;
    PORT
      LAYER M4 ;
        RECT  0 22.896 0.084 22.92 ;
    END
  END b[4]
  PIN b[50]
    DIRECTION OUTPUT ;
    USE SIGNAL ;
    PORT
      LAYER M4 ;
        RECT  0 21.168 0.084 21.192 ;
    END
  END b[50]
  PIN b[51]
    DIRECTION OUTPUT ;
    USE SIGNAL ;
    PORT
      LAYER M4 ;
        RECT  0 21.264 0.084 21.288 ;
    END
  END b[51]
  PIN b[52]
    DIRECTION OUTPUT ;
    USE SIGNAL ;
    PORT
      LAYER M4 ;
        RECT  0 21.36 0.084 21.384 ;
    END
  END b[52]
  PIN b[53]
    DIRECTION OUTPUT ;
    USE SIGNAL ;
    PORT
      LAYER M4 ;
        RECT  0 21.456 0.084 21.48 ;
    END
  END b[53]
  PIN b[54]
    DIRECTION OUTPUT ;
    USE SIGNAL ;
    PORT
      LAYER M4 ;
        RECT  0 21.552 0.084 21.576 ;
    END
  END b[54]
  PIN b[55]
    DIRECTION OUTPUT ;
    USE SIGNAL ;
    PORT
      LAYER M4 ;
        RECT  0 21.648 0.084 21.672 ;
    END
  END b[55]
  PIN b[56]
    DIRECTION OUTPUT ;
    USE SIGNAL ;
    PORT
      LAYER M4 ;
        RECT  0 21.744 0.084 21.768 ;
    END
  END b[56]
  PIN b[57]
    DIRECTION OUTPUT ;
    USE SIGNAL ;
    PORT
      LAYER M4 ;
        RECT  0 21.84 0.084 21.864 ;
    END
  END b[57]
  PIN b[58]
    DIRECTION OUTPUT ;
    USE SIGNAL ;
    PORT
      LAYER M4 ;
        RECT  0 21.936 0.084 21.96 ;
    END
  END b[58]
  PIN b[59]
    DIRECTION OUTPUT ;
    USE SIGNAL ;
    PORT
      LAYER M4 ;
        RECT  0 22.032 0.084 22.056 ;
    END
  END b[59]
  PIN b[5]
    DIRECTION OUTPUT ;
    USE SIGNAL ;
    PORT
      LAYER M4 ;
        RECT  0 22.992 0.084 23.016 ;
    END
  END b[5]
  PIN b[60]
    DIRECTION OUTPUT ;
    USE SIGNAL ;
    PORT
      LAYER M4 ;
        RECT  0 22.128 0.084 22.152 ;
    END
  END b[60]
  PIN b[61]
    DIRECTION OUTPUT ;
    USE SIGNAL ;
    PORT
      LAYER M4 ;
        RECT  0 22.224 0.084 22.248 ;
    END
  END b[61]
  PIN b[62]
    DIRECTION OUTPUT ;
    USE SIGNAL ;
    PORT
      LAYER M4 ;
        RECT  0 22.32 0.084 22.344 ;
    END
  END b[62]
  PIN b[63]
    DIRECTION OUTPUT ;
    USE SIGNAL ;
    PORT
      LAYER M4 ;
        RECT  0 22.416 0.084 22.44 ;
    END
  END b[63]
  PIN b[64]
    DIRECTION OUTPUT ;
    USE SIGNAL ;
    PORT
      LAYER M4 ;
        RECT  0 16.368 0.084 16.392 ;
    END
  END b[64]
  PIN b[65]
    DIRECTION OUTPUT ;
    USE SIGNAL ;
    PORT
      LAYER M4 ;
        RECT  0 16.464 0.084 16.488 ;
    END
  END b[65]
  PIN b[66]
    DIRECTION OUTPUT ;
    USE SIGNAL ;
    PORT
      LAYER M4 ;
        RECT  0 16.56 0.084 16.584 ;
    END
  END b[66]
  PIN b[67]
    DIRECTION OUTPUT ;
    USE SIGNAL ;
    PORT
      LAYER M4 ;
        RECT  0 16.656 0.084 16.68 ;
    END
  END b[67]
  PIN b[68]
    DIRECTION OUTPUT ;
    USE SIGNAL ;
    PORT
      LAYER M4 ;
        RECT  0 16.752 0.084 16.776 ;
    END
  END b[68]
  PIN b[69]
    DIRECTION OUTPUT ;
    USE SIGNAL ;
    PORT
      LAYER M4 ;
        RECT  0 16.848 0.084 16.872 ;
    END
  END b[69]
  PIN b[6]
    DIRECTION OUTPUT ;
    USE SIGNAL ;
    PORT
      LAYER M4 ;
        RECT  0 23.088 0.084 23.112 ;
    END
  END b[6]
  PIN b[70]
    DIRECTION OUTPUT ;
    USE SIGNAL ;
    PORT
      LAYER M4 ;
        RECT  0 16.944 0.084 16.968 ;
    END
  END b[70]
  PIN b[71]
    DIRECTION OUTPUT ;
    USE SIGNAL ;
    PORT
      LAYER M4 ;
        RECT  0 17.04 0.084 17.064 ;
    END
  END b[71]
  PIN b[72]
    DIRECTION OUTPUT ;
    USE SIGNAL ;
    PORT
      LAYER M4 ;
        RECT  0 17.136 0.084 17.16 ;
    END
  END b[72]
  PIN b[73]
    DIRECTION OUTPUT ;
    USE SIGNAL ;
    PORT
      LAYER M4 ;
        RECT  0 17.232 0.084 17.256 ;
    END
  END b[73]
  PIN b[74]
    DIRECTION OUTPUT ;
    USE SIGNAL ;
    PORT
      LAYER M4 ;
        RECT  0 17.328 0.084 17.352 ;
    END
  END b[74]
  PIN b[75]
    DIRECTION OUTPUT ;
    USE SIGNAL ;
    PORT
      LAYER M4 ;
        RECT  0 17.424 0.084 17.448 ;
    END
  END b[75]
  PIN b[76]
    DIRECTION OUTPUT ;
    USE SIGNAL ;
    PORT
      LAYER M4 ;
        RECT  0 17.52 0.084 17.544 ;
    END
  END b[76]
  PIN b[77]
    DIRECTION OUTPUT ;
    USE SIGNAL ;
    PORT
      LAYER M4 ;
        RECT  0 17.616 0.084 17.64 ;
    END
  END b[77]
  PIN b[78]
    DIRECTION OUTPUT ;
    USE SIGNAL ;
    PORT
      LAYER M4 ;
        RECT  0 17.712 0.084 17.736 ;
    END
  END b[78]
  PIN b[79]
    DIRECTION OUTPUT ;
    USE SIGNAL ;
    PORT
      LAYER M4 ;
        RECT  0 17.808 0.084 17.832 ;
    END
  END b[79]
  PIN b[7]
    DIRECTION OUTPUT ;
    USE SIGNAL ;
    PORT
      LAYER M4 ;
        RECT  0 23.184 0.084 23.208 ;
    END
  END b[7]
  PIN b[80]
    DIRECTION OUTPUT ;
    USE SIGNAL ;
    PORT
      LAYER M4 ;
        RECT  0 17.904 0.084 17.928 ;
    END
  END b[80]
  PIN b[81]
    DIRECTION OUTPUT ;
    USE SIGNAL ;
    PORT
      LAYER M4 ;
        RECT  0 18 0.084 18.024 ;
    END
  END b[81]
  PIN b[82]
    DIRECTION OUTPUT ;
    USE SIGNAL ;
    PORT
      LAYER M4 ;
        RECT  0 18.096 0.084 18.12 ;
    END
  END b[82]
  PIN b[83]
    DIRECTION OUTPUT ;
    USE SIGNAL ;
    PORT
      LAYER M4 ;
        RECT  0 18.192 0.084 18.216 ;
    END
  END b[83]
  PIN b[84]
    DIRECTION OUTPUT ;
    USE SIGNAL ;
    PORT
      LAYER M4 ;
        RECT  0 18.288 0.084 18.312 ;
    END
  END b[84]
  PIN b[85]
    DIRECTION OUTPUT ;
    USE SIGNAL ;
    PORT
      LAYER M4 ;
        RECT  0 18.384 0.084 18.408 ;
    END
  END b[85]
  PIN b[86]
    DIRECTION OUTPUT ;
    USE SIGNAL ;
    PORT
      LAYER M4 ;
        RECT  0 18.48 0.084 18.504 ;
    END
  END b[86]
  PIN b[87]
    DIRECTION OUTPUT ;
    USE SIGNAL ;
    PORT
      LAYER M4 ;
        RECT  0 18.576 0.084 18.6 ;
    END
  END b[87]
  PIN b[88]
    DIRECTION OUTPUT ;
    USE SIGNAL ;
    PORT
      LAYER M4 ;
        RECT  0 18.672 0.084 18.696 ;
    END
  END b[88]
  PIN b[89]
    DIRECTION OUTPUT ;
    USE SIGNAL ;
    PORT
      LAYER M4 ;
        RECT  0 18.768 0.084 18.792 ;
    END
  END b[89]
  PIN b[8]
    DIRECTION OUTPUT ;
    USE SIGNAL ;
    PORT
      LAYER M4 ;
        RECT  0 23.28 0.084 23.304 ;
    END
  END b[8]
  PIN b[90]
    DIRECTION OUTPUT ;
    USE SIGNAL ;
    PORT
      LAYER M4 ;
        RECT  0 18.864 0.084 18.888 ;
    END
  END b[90]
  PIN b[91]
    DIRECTION OUTPUT ;
    USE SIGNAL ;
    PORT
      LAYER M4 ;
        RECT  0 18.96 0.084 18.984 ;
    END
  END b[91]
  PIN b[92]
    DIRECTION OUTPUT ;
    USE SIGNAL ;
    PORT
      LAYER M4 ;
        RECT  0 19.056 0.084 19.08 ;
    END
  END b[92]
  PIN b[93]
    DIRECTION OUTPUT ;
    USE SIGNAL ;
    PORT
      LAYER M4 ;
        RECT  0 19.152 0.084 19.176 ;
    END
  END b[93]
  PIN b[94]
    DIRECTION OUTPUT ;
    USE SIGNAL ;
    PORT
      LAYER M4 ;
        RECT  0 19.248 0.084 19.272 ;
    END
  END b[94]
  PIN b[95]
    DIRECTION OUTPUT ;
    USE SIGNAL ;
    PORT
      LAYER M4 ;
        RECT  0 19.344 0.084 19.368 ;
    END
  END b[95]
  PIN b[96]
    DIRECTION OUTPUT ;
    USE SIGNAL ;
    PORT
      LAYER M4 ;
        RECT  0 13.296 0.084 13.32 ;
    END
  END b[96]
  PIN b[97]
    DIRECTION OUTPUT ;
    USE SIGNAL ;
    PORT
      LAYER M4 ;
        RECT  0 13.392 0.084 13.416 ;
    END
  END b[97]
  PIN b[98]
    DIRECTION OUTPUT ;
    USE SIGNAL ;
    PORT
      LAYER M4 ;
        RECT  0 13.488 0.084 13.512 ;
    END
  END b[98]
  PIN b[99]
    DIRECTION OUTPUT ;
    USE SIGNAL ;
    PORT
      LAYER M4 ;
        RECT  0 13.584 0.084 13.608 ;
    END
  END b[99]
  PIN b[9]
    DIRECTION OUTPUT ;
    USE SIGNAL ;
    PORT
      LAYER M4 ;
        RECT  0 23.376 0.084 23.4 ;
    END
  END b[9]
  PIN ck
    DIRECTION INPUT ;
    USE SIGNAL ;
    PORT
      LAYER M4 ;
        RECT  21.516 20.688 21.6 20.712 ;
    END
  END ck
  PIN ck_o
    DIRECTION OUTPUT ;
    USE SIGNAL ;
    PORT
      LAYER M4 ;
        RECT  0 28.464 0.084 28.488 ;
    END
  END ck_o
  PIN eb
    DIRECTION OUTPUT ;
    USE SIGNAL ;
    PORT
      LAYER M4 ;
        RECT  0 28.56 0.084 28.584 ;
    END
  END eb
  PIN en
    DIRECTION INPUT ;
    USE SIGNAL ;
    PORT
      LAYER M4 ;
        RECT  21.516 20.784 21.6 20.808 ;
    END
  END en
  PIN VDD
    DIRECTION INOUT ;
    USE POWER ;
    PORT
      LAYER M5 ;
        RECT  18.792 2.151 18.912 30.249 ;
        RECT  16.092 2.151 16.212 30.249 ;
        RECT  13.392 2.151 13.512 30.249 ;
        RECT  10.692 2.151 10.812 30.249 ;
        RECT  7.992 2.151 8.112 30.249 ;
        RECT  5.292 2.151 5.412 30.249 ;
        RECT  2.592 2.151 2.712 30.249 ;
    END
  END VDD
  PIN VSS
    DIRECTION INOUT ;
    USE GROUND ;
    PORT
      LAYER M5 ;
        RECT  18.6 2.137 18.72 30.263 ;
        RECT  15.9 2.137 16.02 30.263 ;
        RECT  13.2 2.137 13.32 30.263 ;
        RECT  10.5 2.137 10.62 30.263 ;
        RECT  7.8 2.137 7.92 30.263 ;
        RECT  5.1 2.137 5.22 30.263 ;
        RECT  2.4 2.137 2.52 30.263 ;
    END
  END VSS
  # OT_OBS_CLOSED layer=M5 d_um=1.536 added=18
  OBS
    LAYER RVTN ;
     RECT  2.16 2.16 19.44 2.295 ;
     RECT  2.16 2.565 19.44 2.835 ;
     RECT  2.16 3.105 19.44 3.375 ;
     RECT  2.16 3.645 19.44 3.915 ;
     RECT  2.16 4.185 19.44 4.455 ;
     RECT  2.16 4.725 19.44 4.995 ;
     RECT  2.16 5.265 19.44 5.535 ;
     RECT  2.16 5.805 19.44 6.075 ;
     RECT  2.16 6.345 19.44 6.615 ;
     RECT  2.16 6.885 19.44 7.155 ;
     RECT  2.16 7.425 19.44 7.695 ;
     RECT  2.16 7.965 19.44 8.235 ;
     RECT  2.16 8.505 19.44 8.775 ;
     RECT  2.16 9.045 19.44 9.315 ;
     RECT  2.16 9.585 19.44 9.855 ;
     RECT  2.16 10.125 19.44 10.395 ;
     RECT  2.16 10.665 19.44 10.935 ;
     RECT  2.16 11.205 19.44 11.475 ;
     RECT  2.16 11.745 19.44 12.015 ;
     RECT  2.16 12.285 19.44 12.555 ;
     RECT  2.16 12.825 19.44 13.095 ;
     RECT  2.16 13.365 19.44 13.635 ;
     RECT  2.16 13.905 19.44 14.175 ;
     RECT  2.16 14.445 19.44 14.715 ;
     RECT  2.16 14.985 19.44 15.255 ;
     RECT  2.16 15.525 19.44 15.795 ;
     RECT  2.16 16.065 19.44 16.335 ;
     RECT  2.16 16.605 19.44 16.875 ;
     RECT  2.16 17.145 19.44 17.415 ;
     RECT  2.16 17.685 19.44 17.955 ;
     RECT  2.16 18.225 19.44 18.495 ;
     RECT  2.16 18.765 19.44 19.035 ;
     RECT  2.16 19.305 19.44 19.575 ;
     RECT  2.16 19.845 19.44 20.115 ;
     RECT  2.16 20.385 19.44 20.655 ;
     RECT  2.16 20.925 19.44 21.195 ;
     RECT  2.16 21.465 19.44 21.735 ;
     RECT  2.16 22.005 19.44 22.275 ;
     RECT  2.16 22.545 19.44 22.815 ;
     RECT  2.16 23.085 19.44 23.355 ;
     RECT  2.16 23.625 19.44 23.895 ;
     RECT  2.16 24.165 19.44 24.435 ;
     RECT  2.16 24.705 19.44 24.975 ;
     RECT  2.16 25.245 19.44 25.515 ;
     RECT  2.16 25.785 19.44 26.055 ;
     RECT  2.16 26.325 19.44 26.595 ;
     RECT  2.16 26.865 19.44 27.135 ;
     RECT  2.16 27.405 19.44 27.675 ;
     RECT  2.16 27.945 19.44 28.215 ;
     RECT  2.16 28.485 19.44 28.755 ;
     RECT  2.16 29.025 19.44 29.295 ;
     RECT  2.16 29.565 19.44 29.835 ;
     RECT  2.16 30.105 19.44 30.24 ;
    LAYER RVTP ;
     RECT  2.16 2.295 19.44 2.565 ;
     RECT  2.16 2.835 19.44 3.105 ;
     RECT  2.16 3.375 19.44 3.645 ;
     RECT  2.16 3.915 19.44 4.185 ;
     RECT  2.16 4.455 19.44 4.725 ;
     RECT  2.16 4.995 19.44 5.265 ;
     RECT  2.16 5.535 19.44 5.805 ;
     RECT  2.16 6.075 19.44 6.345 ;
     RECT  2.16 6.615 19.44 6.885 ;
     RECT  2.16 7.155 19.44 7.425 ;
     RECT  2.16 7.695 19.44 7.965 ;
     RECT  2.16 8.235 19.44 8.505 ;
     RECT  2.16 8.775 19.44 9.045 ;
     RECT  2.16 9.315 19.44 9.585 ;
     RECT  2.16 9.855 19.44 10.125 ;
     RECT  2.16 10.395 19.44 10.665 ;
     RECT  2.16 10.935 19.44 11.205 ;
     RECT  2.16 11.475 19.44 11.745 ;
     RECT  2.16 12.015 19.44 12.285 ;
     RECT  2.16 12.555 19.44 12.825 ;
     RECT  2.16 13.095 19.44 13.365 ;
     RECT  2.16 13.635 19.44 13.905 ;
     RECT  2.16 14.175 19.44 14.445 ;
     RECT  2.16 14.715 19.44 14.985 ;
     RECT  2.16 15.255 19.44 15.525 ;
     RECT  2.16 15.795 19.44 16.065 ;
     RECT  2.16 16.335 19.44 16.605 ;
     RECT  2.16 16.875 19.44 17.145 ;
     RECT  2.16 17.415 19.44 17.685 ;
     RECT  2.16 17.955 19.44 18.225 ;
     RECT  2.16 18.495 19.44 18.765 ;
     RECT  2.16 19.035 19.44 19.305 ;
     RECT  2.16 19.575 19.44 19.845 ;
     RECT  2.16 20.115 19.44 20.385 ;
     RECT  2.16 20.655 19.44 20.925 ;
     RECT  2.16 21.195 19.44 21.465 ;
     RECT  2.16 21.735 19.44 22.005 ;
     RECT  2.16 22.275 19.44 22.545 ;
     RECT  2.16 22.815 19.44 23.085 ;
     RECT  2.16 23.355 19.44 23.625 ;
     RECT  2.16 23.895 19.44 24.165 ;
     RECT  2.16 24.435 19.44 24.705 ;
     RECT  2.16 24.975 19.44 25.245 ;
     RECT  2.16 25.515 19.44 25.785 ;
     RECT  2.16 26.055 19.44 26.325 ;
     RECT  2.16 26.595 19.44 26.865 ;
     RECT  2.16 27.135 19.44 27.405 ;
     RECT  2.16 27.675 19.44 27.945 ;
     RECT  2.16 28.215 19.44 28.485 ;
     RECT  2.16 28.755 19.44 29.025 ;
     RECT  2.16 29.295 19.44 29.565 ;
     RECT  2.16 29.835 19.44 30.105 ;
    LAYER M1 ;
     RECT  2.16 2.151 19.44 30.249 ;
    LAYER M2 ;
     RECT  0.031 15.966 0.103 15.984 ;
     RECT  0.103 23.211 0.139 23.229 ;
     RECT  0.103 15.156 0.203 15.984 ;
     RECT  0.103 18.621 0.203 18.639 ;
     RECT  0.103 19.62 0.203 19.638 ;
     RECT  0.103 21.402 0.203 21.42 ;
     RECT  0.031 8.478 0.319 8.496 ;
     RECT  0.139 23.166 0.319 23.229 ;
     RECT  0.319 23.166 0.355 23.58 ;
     RECT  0.319 24.714 0.355 24.732 ;
     RECT  0.319 8.244 0.391 8.496 ;
     RECT  0.355 23.094 0.391 24.732 ;
     RECT  0.355 27.756 0.391 27.774 ;
     RECT  0.391 27.648 0.427 27.774 ;
     RECT  0.203 15.876 0.463 15.984 ;
     RECT  0.391 22.446 0.463 24.732 ;
     RECT  0.427 27.342 0.463 27.774 ;
     RECT  0.463 15.876 0.499 16.434 ;
     RECT  0.103 17.226 0.499 17.244 ;
     RECT  0.463 21.438 0.499 24.732 ;
     RECT  0.463 27.216 0.499 27.774 ;
     RECT  0.463 13.806 0.535 13.824 ;
     RECT  0.499 27.108 0.535 27.774 ;
     RECT  0.391 8.208 1.975 8.496 ;
     RECT  1.975 7.866 2.16 8.496 ;
     RECT  0.499 11.214 2.16 11.232 ;
     RECT  0.535 13.068 2.16 14.238 ;
     RECT  0.499 15.876 2.16 18.144 ;
     RECT  0.499 21.438 2.16 24.894 ;
     RECT  0.535 27.108 2.16 27.864 ;
     RECT  2.16 2.151 19.44 30.249 ;
     RECT  19.44 20.16 19.895 21.258 ;
     RECT  19.895 20.358 19.931 21.258 ;
     RECT  19.44 6.696 19.967 19.134 ;
     RECT  19.967 6.696 20.003 6.84 ;
     RECT  19.967 7.74 20.219 19.134 ;
     RECT  20.219 7.866 20.327 19.134 ;
     RECT  20.327 12.258 20.435 19.134 ;
     RECT  19.931 20.358 20.435 20.988 ;
     RECT  20.327 7.866 20.471 11.232 ;
     RECT  20.471 7.866 20.507 8.874 ;
     RECT  20.471 10.908 20.507 11.232 ;
     RECT  20.435 12.258 20.507 13.086 ;
     RECT  20.435 14.148 20.507 17.748 ;
     RECT  20.435 18.504 20.507 19.134 ;
     RECT  20.003 6.696 20.543 6.714 ;
     RECT  20.471 9.63 20.543 10.152 ;
     RECT  20.507 10.908 20.543 10.998 ;
     RECT  20.507 18.504 20.543 19.098 ;
     RECT  20.435 20.826 20.543 20.988 ;
     RECT  20.507 7.866 20.579 8.064 ;
     RECT  20.543 18.846 20.579 19.098 ;
     RECT  20.543 20.898 20.579 20.988 ;
     RECT  20.579 8.046 20.615 8.064 ;
     RECT  20.543 10.908 21.443 10.926 ;
     RECT  20.507 14.724 21.443 17.406 ;
     RECT  20.579 18.846 21.479 19.026 ;
     RECT  20.543 9.63 21.515 9.648 ;
     RECT  20.507 13.068 21.515 13.086 ;
     RECT  21.443 14.724 21.515 17.1 ;
     RECT  21.479 18.846 21.515 18.864 ;
     RECT  20.579 20.97 21.515 20.988 ;
    LAYER M3 ;
     RECT  2.415 2.143 2.505 2.413 ;
     RECT  5.115 2.143 5.205 2.413 ;
     RECT  7.815 2.143 7.905 2.413 ;
     RECT  10.515 2.143 10.605 2.413 ;
     RECT  13.215 2.143 13.305 2.413 ;
     RECT  15.915 2.143 16.005 2.413 ;
     RECT  18.615 2.143 18.705 2.413 ;
     RECT  2.415 2.413 2.697 6.043 ;
     RECT  5.115 2.413 5.397 6.139 ;
     RECT  15.915 2.413 16.197 6.151 ;
     RECT  18.615 2.413 18.897 6.151 ;
     RECT  2.415 6.043 2.79 6.173 ;
     RECT  5.115 6.139 5.49 6.179 ;
     RECT  15.915 6.151 16.614 6.241 ;
     RECT  15.915 6.241 16.974 6.421 ;
     RECT  5.115 6.179 5.397 6.511 ;
     RECT  13.215 2.413 13.497 6.511 ;
     RECT  5.004 6.511 5.397 6.557 ;
     RECT  6.84 6.523 6.858 6.653 ;
     RECT  18.36 6.151 18.897 6.655 ;
     RECT  18.36 6.655 19.422 6.691 ;
     RECT  18.216 6.691 19.422 6.817 ;
     RECT  20.52 6.691 20.538 6.817 ;
     RECT  14.832 6.523 14.85 6.961 ;
     RECT  18.216 6.817 20.538 6.989 ;
     RECT  14.616 6.961 14.85 7.115 ;
     RECT  15.915 6.421 17.442 7.189 ;
     RECT  18.216 6.989 20.214 7.189 ;
     RECT  13.104 6.511 13.497 7.321 ;
     RECT  15.915 7.189 20.214 7.339 ;
     RECT  13.104 7.321 14.058 7.357 ;
     RECT  2.415 6.173 2.697 7.387 ;
     RECT  15.732 7.339 20.214 7.421 ;
     RECT  14.796 7.115 14.85 7.465 ;
     RECT  15.732 7.421 17.838 7.465 ;
     RECT  7.815 2.413 8.097 7.501 ;
     RECT  10.515 2.413 10.797 7.501 ;
     RECT  7.776 7.501 8.097 7.619 ;
     RECT  2.415 7.387 2.898 7.861 ;
     RECT  12.924 7.357 14.058 7.861 ;
     RECT  18.615 7.421 20.214 7.861 ;
     RECT  1.98 7.861 2.898 7.933 ;
     RECT  18.615 7.861 20.574 7.949 ;
     RECT  5.115 6.557 5.397 7.969 ;
     RECT  10.515 7.501 10.854 7.969 ;
     RECT  12.528 7.861 14.058 8.011 ;
     RECT  14.796 7.465 17.838 8.011 ;
     RECT  5.115 7.969 5.814 8.041 ;
     RECT  10.515 7.969 10.926 8.041 ;
     RECT  19.908 7.949 20.574 8.041 ;
     RECT  5.115 8.041 5.994 8.131 ;
     RECT  10.515 8.041 11.286 8.131 ;
     RECT  12.528 8.011 17.838 8.131 ;
     RECT  9.648 8.005 9.666 8.159 ;
     RECT  10.515 8.131 17.838 8.231 ;
     RECT  0.396 8.203 0.414 8.239 ;
     RECT  19.908 8.041 20.61 8.333 ;
     RECT  3.78 7.195 3.798 8.401 ;
     RECT  9.72 8.311 9.738 8.465 ;
     RECT  0.324 8.239 0.414 8.473 ;
     RECT  7.815 7.619 8.097 8.473 ;
     RECT  10.515 8.231 17.73 8.473 ;
     RECT  7.524 8.473 8.097 8.609 ;
     RECT  1.98 7.933 2.97 9.121 ;
     RECT  3.744 8.401 3.798 9.121 ;
     RECT  18.615 7.949 18.954 9.211 ;
     RECT  19.908 8.333 20.502 9.259 ;
     RECT  18.504 9.211 18.954 9.283 ;
     RECT  18.504 9.283 18.99 9.319 ;
     RECT  19.908 9.259 20.538 9.319 ;
     RECT  1.98 9.121 3.798 9.391 ;
     RECT  9.936 8.473 17.73 9.391 ;
     RECT  18.504 9.319 20.538 9.391 ;
     RECT  1.98 9.391 4.266 9.509 ;
     RECT  21.492 8.875 21.51 9.653 ;
     RECT  9.936 9.391 20.538 10.157 ;
     RECT  9.936 10.157 20.466 10.229 ;
     RECT  1.98 9.509 4.014 10.291 ;
     RECT  5.115 8.131 6.066 10.291 ;
     RECT  9.936 10.229 14.922 10.349 ;
     RECT  6.84 10.327 6.858 10.427 ;
     RECT  15.696 10.229 20.466 10.891 ;
     RECT  21.42 10.795 21.438 10.931 ;
     RECT  15.696 10.891 20.538 11.003 ;
     RECT  7.815 8.609 8.097 11.173 ;
     RECT  9.936 10.349 14.886 11.173 ;
     RECT  15.696 11.003 20.502 11.173 ;
     RECT  1.98 10.291 6.066 11.179 ;
     RECT  7.344 11.173 8.097 11.179 ;
     RECT  0.036 8.473 0.414 11.209 ;
     RECT  9.936 11.173 20.502 11.237 ;
     RECT  9.144 11.245 9.162 11.371 ;
     RECT  9.936 11.237 20.322 11.371 ;
     RECT  9.144 11.371 20.322 11.399 ;
     RECT  9.252 11.399 20.322 11.789 ;
     RECT  9.252 11.789 18.897 11.975 ;
     RECT  19.8 11.789 20.322 12.235 ;
     RECT  19.8 12.235 20.502 12.461 ;
     RECT  19.872 12.461 20.502 12.551 ;
     RECT  14.472 11.975 18.897 12.619 ;
     RECT  14.472 12.619 18.99 12.821 ;
     RECT  9.252 11.975 13.734 12.991 ;
     RECT  14.472 12.821 18.954 12.991 ;
     RECT  1.98 11.179 8.097 13.055 ;
     RECT  0.036 11.209 0.522 13.063 ;
     RECT  21.492 12.907 21.51 13.091 ;
     RECT  19.872 12.551 20.322 13.291 ;
     RECT  19.836 13.291 20.322 13.387 ;
     RECT  19.836 13.387 20.43 13.405 ;
     RECT  0.036 13.063 0.558 13.675 ;
     RECT  9.252 12.991 18.954 13.675 ;
     RECT  19.8 13.405 20.43 13.675 ;
     RECT  9.252 13.675 20.43 13.865 ;
     RECT  9.468 13.865 20.43 13.963 ;
     RECT  7.02 13.055 8.097 14.071 ;
     RECT  9.468 13.963 20.502 14.093 ;
     RECT  9.468 14.093 19.026 14.171 ;
     RECT  19.908 14.093 20.502 14.243 ;
     RECT  6.84 14.071 8.097 14.251 ;
     RECT  6.804 14.251 8.097 14.477 ;
     RECT  21.492 13.867 21.51 14.539 ;
     RECT  0.036 13.675 0.666 14.573 ;
     RECT  1.98 13.055 6.066 14.791 ;
     RECT  21.456 14.539 21.51 14.819 ;
     RECT  9.936 14.171 19.026 14.827 ;
     RECT  0.036 14.573 0.486 14.861 ;
     RECT  7.02 14.477 8.097 14.957 ;
     RECT  9.936 14.827 19.386 15.557 ;
     RECT  20.196 14.243 20.502 15.691 ;
     RECT  19.836 15.691 20.502 15.763 ;
     RECT  7.128 14.957 8.097 15.821 ;
     RECT  19.836 15.763 20.538 15.821 ;
     RECT  0.036 14.861 0.414 15.871 ;
     RECT  1.98 14.791 6.138 15.979 ;
     RECT  0.036 15.871 0.558 15.989 ;
     RECT  1.98 15.979 6.858 16.157 ;
     RECT  21.492 14.819 21.51 16.267 ;
     RECT  9.936 15.557 18.897 16.303 ;
     RECT  19.836 15.821 20.502 16.303 ;
     RECT  1.98 16.157 6.75 16.349 ;
     RECT  0.108 15.989 0.558 16.493 ;
     RECT  9.936 16.303 20.502 16.529 ;
     RECT  1.98 16.349 6.066 16.601 ;
     RECT  9.936 16.529 18.897 16.835 ;
     RECT  1.98 16.601 5.814 17.105 ;
     RECT  21.42 16.267 21.51 17.105 ;
     RECT  1.98 17.105 5.397 17.165 ;
     RECT  7.815 15.821 8.097 17.221 ;
     RECT  7.815 17.221 8.73 17.339 ;
     RECT  2.304 17.165 5.397 17.357 ;
     RECT  21.42 17.105 21.438 17.411 ;
     RECT  3.564 17.357 5.397 17.483 ;
     RECT  0.108 16.493 0.522 17.549 ;
     RECT  0.504 17.549 0.522 17.581 ;
     RECT  2.304 17.357 2.826 17.645 ;
     RECT  19.908 16.529 20.502 17.707 ;
     RECT  10.512 16.835 18.897 17.761 ;
     RECT  6.84 17.419 6.858 17.789 ;
     RECT  10.476 17.761 18.954 17.803 ;
     RECT  0.504 17.581 0.558 17.899 ;
     RECT  3.888 17.483 5.397 17.915 ;
     RECT  10.476 17.803 19.026 18.023 ;
     RECT  7.815 17.339 8.658 18.121 ;
     RECT  0.504 17.899 0.666 18.125 ;
     RECT  3.996 17.915 5.397 18.185 ;
     RECT  7.38 18.121 8.658 18.185 ;
     RECT  10.515 18.023 19.026 18.283 ;
     RECT  19.908 17.707 20.538 18.283 ;
     RECT  0.504 18.125 0.558 18.317 ;
     RECT  4.176 18.185 5.397 18.317 ;
     RECT  2.304 17.645 2.697 18.413 ;
     RECT  0.504 18.317 0.522 18.604 ;
     RECT  2.376 18.413 2.697 18.605 ;
     RECT  21.492 18.571 21.51 18.667 ;
     RECT  0.108 18.604 0.522 18.701 ;
     RECT  0.144 18.701 0.522 18.797 ;
     RECT  21.312 18.667 21.51 18.797 ;
     RECT  10.515 18.283 20.538 18.833 ;
     RECT  20.484 18.833 20.538 18.859 ;
     RECT  21.456 18.797 21.51 18.869 ;
     RECT  4.464 18.317 5.397 18.995 ;
     RECT  21.456 18.869 21.474 19.031 ;
     RECT  10.515 18.833 19.386 19.067 ;
     RECT  0.144 18.797 0.234 19.085 ;
     RECT  2.415 18.605 2.697 19.099 ;
     RECT  20.484 18.859 20.574 19.103 ;
     RECT  2.415 19.099 2.79 19.139 ;
     RECT  3.996 19.099 4.014 19.139 ;
     RECT  20.484 19.103 20.502 19.139 ;
     RECT  0.144 19.085 0.198 19.612 ;
     RECT  0.108 19.612 0.198 19.757 ;
     RECT  0.18 19.757 0.198 19.805 ;
     RECT  2.415 19.139 2.697 19.912 ;
     RECT  5.115 18.995 5.397 19.912 ;
     RECT  10.515 19.067 19.35 19.915 ;
     RECT  2.304 19.912 2.697 20.011 ;
     RECT  2.304 20.011 2.97 20.048 ;
     RECT  7.38 18.185 8.097 20.059 ;
     RECT  10.515 19.915 19.926 20.107 ;
     RECT  2.415 20.048 2.97 20.141 ;
     RECT  10.515 20.107 20.538 20.237 ;
     RECT  2.415 20.141 2.862 20.333 ;
     RECT  6.84 20.059 8.097 20.333 ;
     RECT  6.84 20.333 6.966 20.381 ;
     RECT  19.908 20.237 20.538 20.395 ;
     RECT  6.948 20.381 6.966 20.477 ;
     RECT  5.004 19.912 5.397 20.489 ;
     RECT  0.216 20.203 0.342 20.683 ;
     RECT  5.115 20.489 5.397 20.821 ;
     RECT  2.415 20.333 2.79 20.861 ;
     RECT  19.908 20.395 20.574 20.921 ;
     RECT  10.515 20.237 19.062 20.957 ;
     RECT  21.492 20.587 21.51 20.993 ;
     RECT  10.515 20.957 18.897 21.029 ;
     RECT  19.908 20.921 19.926 21.263 ;
     RECT  5.115 20.821 5.49 21.299 ;
     RECT  0.144 20.683 0.342 21.388 ;
     RECT  10.515 21.029 11.79 21.425 ;
     RECT  0.108 21.388 0.342 21.433 ;
     RECT  0.108 21.433 0.522 21.541 ;
     RECT  0.108 21.541 0.558 21.581 ;
     RECT  2.415 20.861 2.697 21.631 ;
     RECT  5.115 21.299 5.397 21.631 ;
     RECT  2.304 21.631 2.697 21.677 ;
     RECT  5.004 21.631 5.397 21.677 ;
     RECT  12.564 21.029 18.897 21.677 ;
     RECT  2.415 21.677 2.697 21.979 ;
     RECT  2.415 21.979 2.862 22.109 ;
     RECT  0.144 21.581 0.558 22.315 ;
     RECT  5.115 21.677 5.397 22.441 ;
     RECT  0.144 22.315 0.594 22.445 ;
     RECT  12.996 21.677 18.897 22.505 ;
     RECT  10.515 21.425 11.178 22.549 ;
     RECT  2.415 22.109 2.697 22.603 ;
     RECT  5.115 22.441 5.454 22.603 ;
     RECT  10.515 22.549 11.322 22.621 ;
     RECT  6.84 21.115 6.858 22.637 ;
     RECT  2.304 22.603 2.697 22.649 ;
     RECT  5.004 22.603 5.454 22.649 ;
     RECT  10.515 22.621 11.358 22.795 ;
     RECT  10.515 22.795 11.574 22.981 ;
     RECT  10.515 22.981 11.682 23.069 ;
     RECT  0.144 22.445 0.558 23.206 ;
     RECT  10.515 23.069 11.358 23.279 ;
     RECT  0.108 23.206 0.558 23.309 ;
     RECT  0.18 23.309 0.558 23.357 ;
     RECT  0.324 23.357 0.558 23.899 ;
     RECT  13.104 22.505 18.897 23.971 ;
     RECT  0.324 23.899 0.594 24.077 ;
     RECT  2.415 22.649 2.697 24.331 ;
     RECT  5.115 22.649 5.397 24.331 ;
     RECT  6.84 24.187 6.858 24.331 ;
     RECT  12.528 23.971 18.897 24.365 ;
     RECT  2.304 24.331 2.697 24.368 ;
     RECT  5.004 24.331 5.397 24.368 ;
     RECT  6.84 24.331 6.966 24.461 ;
     RECT  13.215 24.365 18.897 24.461 ;
     RECT  10.515 23.279 10.926 24.502 ;
     RECT  10.515 24.502 10.962 24.701 ;
     RECT  13.215 24.461 16.758 24.701 ;
     RECT  13.215 24.701 16.686 24.935 ;
     RECT  0.324 24.077 0.558 25.325 ;
     RECT  0.324 25.325 0.522 25.421 ;
     RECT  0.324 25.421 0.342 25.517 ;
     RECT  17.856 24.461 18.897 26.491 ;
     RECT  17.712 26.491 18.897 26.699 ;
     RECT  17.712 26.699 17.874 26.789 ;
     RECT  14.976 24.935 16.686 26.941 ;
     RECT  17.712 26.789 17.838 26.941 ;
     RECT  13.215 24.935 14.238 27.103 ;
     RECT  14.976 26.941 17.838 27.103 ;
     RECT  10.515 24.701 10.797 27.139 ;
     RECT  0.504 27.103 0.522 27.175 ;
     RECT  0.504 27.175 0.558 27.211 ;
     RECT  13.215 27.103 17.838 27.239 ;
     RECT  17.208 27.239 17.838 27.329 ;
     RECT  0.468 27.211 0.558 27.337 ;
     RECT  17.208 27.329 17.73 27.365 ;
     RECT  0.432 27.337 0.558 27.643 ;
     RECT  13.215 27.239 16.197 27.707 ;
     RECT  0.396 27.643 0.558 27.751 ;
     RECT  10.515 27.139 10.854 27.751 ;
     RECT  10.515 27.751 10.926 27.869 ;
     RECT  13.215 27.707 14.778 27.869 ;
     RECT  14.256 27.869 14.778 27.941 ;
     RECT  14.256 27.941 14.274 28.013 ;
     RECT  0.36 27.751 0.558 28.301 ;
     RECT  2.415 24.368 2.697 28.381 ;
     RECT  0.36 28.301 0.378 28.397 ;
     RECT  2.415 28.381 2.826 28.555 ;
     RECT  2.304 28.555 2.826 28.831 ;
     RECT  4.068 28.795 4.086 28.831 ;
     RECT  5.115 24.368 5.397 28.831 ;
     RECT  2.304 28.831 5.397 28.859 ;
     RECT  2.415 28.859 5.397 28.949 ;
     RECT  2.415 28.949 3.258 28.973 ;
     RECT  4.068 28.949 4.086 28.985 ;
     RECT  2.415 28.973 2.697 29.987 ;
     RECT  5.115 28.949 5.397 29.987 ;
     RECT  7.815 20.333 8.097 29.987 ;
     RECT  10.515 27.869 10.797 29.987 ;
     RECT  13.215 27.869 13.497 29.987 ;
     RECT  15.915 27.707 16.197 29.987 ;
     RECT  18.615 26.699 18.897 29.987 ;
     RECT  2.415 29.987 2.505 30.257 ;
     RECT  5.115 29.987 5.205 30.257 ;
     RECT  7.815 29.987 7.905 30.257 ;
     RECT  10.515 29.987 10.605 30.257 ;
     RECT  13.215 29.987 13.305 30.257 ;
     RECT  15.915 29.987 16.005 30.257 ;
     RECT  18.615 29.987 18.705 30.257 ;
    LAYER M4 ;
     RECT  0.133 6.048 0.181 6.072 ;
     RECT  0.084 13.296 0.353 13.32 ;
     RECT  0.06 13.32 0.353 13.392 ;
     RECT  0.084 13.392 0.353 13.416 ;
     RECT  0.06 13.416 0.353 13.488 ;
     RECT  0.084 13.488 0.353 13.512 ;
     RECT  0.06 13.512 0.353 13.584 ;
     RECT  0.084 13.584 0.353 13.608 ;
     RECT  0.06 13.608 0.353 13.68 ;
     RECT  0.084 13.68 0.353 13.704 ;
     RECT  0.06 13.704 0.353 13.776 ;
     RECT  0.084 13.776 0.353 13.8 ;
     RECT  0.06 13.8 0.353 13.872 ;
     RECT  0.084 13.872 0.353 13.896 ;
     RECT  0.06 13.896 0.353 13.968 ;
     RECT  0.084 13.968 0.353 13.992 ;
     RECT  0.06 13.992 0.353 14.064 ;
     RECT  0.084 14.064 0.353 14.088 ;
     RECT  0.06 14.088 0.353 14.16 ;
     RECT  0.084 14.16 0.353 14.184 ;
     RECT  0.06 14.184 0.353 14.256 ;
     RECT  0.084 14.256 0.353 14.28 ;
     RECT  0.06 14.28 0.353 14.352 ;
     RECT  0.084 14.352 0.353 14.376 ;
     RECT  0.06 14.376 0.353 14.448 ;
     RECT  0.084 14.448 0.353 14.472 ;
     RECT  0.06 14.472 0.353 14.544 ;
     RECT  0.084 14.544 0.353 14.568 ;
     RECT  0.06 14.568 0.353 14.64 ;
     RECT  0.084 14.64 0.353 14.664 ;
     RECT  0.06 14.664 0.353 14.736 ;
     RECT  0.084 14.736 0.353 14.76 ;
     RECT  0.06 14.76 0.353 14.832 ;
     RECT  0.084 14.832 0.353 14.856 ;
     RECT  0.06 14.856 0.353 14.928 ;
     RECT  0.084 14.928 0.353 14.952 ;
     RECT  0.06 14.952 0.353 15.024 ;
     RECT  0.084 15.024 0.353 15.048 ;
     RECT  0.06 15.048 0.353 15.12 ;
     RECT  0.084 15.12 0.353 15.144 ;
     RECT  0.06 15.144 0.353 15.216 ;
     RECT  0.084 15.216 0.353 15.24 ;
     RECT  0.06 15.24 0.353 15.312 ;
     RECT  0.084 15.312 0.353 15.336 ;
     RECT  0.06 15.336 0.353 15.408 ;
     RECT  0.084 15.408 0.353 15.432 ;
     RECT  0.06 15.432 0.353 15.504 ;
     RECT  0.084 15.504 0.353 15.528 ;
     RECT  0.06 15.528 0.353 15.6 ;
     RECT  0.084 15.6 0.353 15.624 ;
     RECT  0.06 15.624 0.353 15.696 ;
     RECT  0.084 15.696 0.353 15.72 ;
     RECT  0.06 15.72 0.353 15.792 ;
     RECT  0.084 15.792 0.353 15.816 ;
     RECT  0.06 15.816 0.353 15.888 ;
     RECT  0.084 15.888 0.353 15.912 ;
     RECT  0.06 15.912 0.353 15.984 ;
     RECT  0.084 15.984 0.353 16.008 ;
     RECT  0.06 16.008 0.353 16.08 ;
     RECT  0.084 16.08 0.353 16.104 ;
     RECT  0.06 16.104 0.353 16.176 ;
     RECT  0.084 16.176 0.353 16.2 ;
     RECT  0.06 16.2 0.353 16.272 ;
     RECT  0.084 16.272 0.353 16.296 ;
     RECT  0.06 16.296 0.353 16.368 ;
     RECT  0.084 16.368 0.353 16.392 ;
     RECT  0.06 16.392 0.353 16.464 ;
     RECT  0.084 16.464 0.353 16.488 ;
     RECT  0.06 16.488 0.353 16.56 ;
     RECT  0.084 16.56 0.353 16.584 ;
     RECT  0.06 16.584 0.353 16.656 ;
     RECT  0.084 16.656 0.353 16.68 ;
     RECT  0.06 16.68 0.353 16.752 ;
     RECT  0.084 16.752 0.353 16.776 ;
     RECT  0.06 16.776 0.353 16.848 ;
     RECT  0.084 16.848 0.353 16.872 ;
     RECT  0.06 16.872 0.353 16.944 ;
     RECT  0.084 16.944 0.353 16.968 ;
     RECT  0.06 16.968 0.353 17.04 ;
     RECT  0.084 17.04 0.353 17.064 ;
     RECT  0.06 17.064 0.353 17.136 ;
     RECT  0.084 17.136 0.353 17.16 ;
     RECT  0.06 17.16 0.353 17.232 ;
     RECT  0.084 17.232 0.353 17.256 ;
     RECT  0.06 17.256 0.353 17.328 ;
     RECT  0.084 17.328 0.353 17.352 ;
     RECT  0.06 17.352 0.353 17.424 ;
     RECT  0.084 17.424 0.353 17.448 ;
     RECT  0.06 17.448 0.353 17.52 ;
     RECT  0.084 17.52 0.353 17.544 ;
     RECT  0.06 17.544 0.353 17.616 ;
     RECT  0.084 17.616 0.353 17.64 ;
     RECT  0.06 17.64 0.353 17.712 ;
     RECT  0.084 17.712 0.353 17.736 ;
     RECT  0.06 17.736 0.353 17.808 ;
     RECT  0.084 17.808 0.353 17.832 ;
     RECT  0.06 17.832 0.353 17.904 ;
     RECT  0.084 17.904 0.353 17.928 ;
     RECT  0.06 17.928 0.353 18 ;
     RECT  0.084 18 0.353 18.024 ;
     RECT  0.06 18.024 0.353 18.096 ;
     RECT  0.084 18.096 0.353 18.12 ;
     RECT  0.06 18.12 0.353 18.192 ;
     RECT  0.084 18.192 0.353 18.216 ;
     RECT  0.06 18.216 0.353 18.288 ;
     RECT  0.084 18.288 0.353 18.312 ;
     RECT  0.06 18.312 0.353 18.384 ;
     RECT  0.084 18.384 0.353 18.408 ;
     RECT  0.06 18.408 0.353 18.48 ;
     RECT  0.084 18.48 0.353 18.504 ;
     RECT  0.06 18.504 0.353 18.576 ;
     RECT  0.084 18.576 0.353 18.6 ;
     RECT  0.06 18.6 0.353 18.672 ;
     RECT  0.084 18.672 0.353 18.696 ;
     RECT  0.06 18.696 0.353 18.768 ;
     RECT  0.084 18.768 0.353 18.792 ;
     RECT  0.06 18.792 0.353 18.864 ;
     RECT  0.084 18.864 0.353 18.888 ;
     RECT  0.06 18.888 0.353 18.96 ;
     RECT  0.084 18.96 0.353 18.984 ;
     RECT  0.06 18.984 0.353 19.056 ;
     RECT  0.084 19.056 0.353 19.08 ;
     RECT  0.06 19.08 0.353 19.152 ;
     RECT  0.084 19.152 0.353 19.176 ;
     RECT  0.06 19.176 0.353 19.248 ;
     RECT  0.084 19.248 0.353 19.272 ;
     RECT  0.06 19.272 0.353 19.344 ;
     RECT  0.084 19.344 0.353 19.368 ;
     RECT  0.06 19.368 0.353 19.44 ;
     RECT  0.084 19.44 0.353 19.464 ;
     RECT  0.06 19.464 0.353 19.536 ;
     RECT  0.084 19.536 0.353 19.56 ;
     RECT  0.06 19.56 0.353 19.632 ;
     RECT  0.084 19.632 0.353 19.656 ;
     RECT  0.06 19.656 0.353 19.728 ;
     RECT  0.084 19.728 0.353 19.752 ;
     RECT  0.06 19.752 0.353 19.824 ;
     RECT  0.084 19.824 0.353 19.848 ;
     RECT  0.06 19.848 0.353 19.92 ;
     RECT  0.084 19.92 0.353 19.944 ;
     RECT  0.06 19.944 0.353 20.016 ;
     RECT  0.084 20.016 0.353 20.04 ;
     RECT  0.06 20.04 0.353 20.112 ;
     RECT  0.084 20.112 0.353 20.136 ;
     RECT  0.06 20.136 0.353 20.208 ;
     RECT  0.084 20.208 0.353 20.232 ;
     RECT  0.06 20.232 0.353 20.304 ;
     RECT  0.084 20.304 0.353 20.328 ;
     RECT  0.06 20.328 0.353 20.4 ;
     RECT  0.084 20.4 0.353 20.424 ;
     RECT  0.06 20.424 0.353 20.496 ;
     RECT  0.084 20.496 0.353 20.52 ;
     RECT  0.06 20.52 0.353 20.592 ;
     RECT  0.084 20.592 0.353 20.616 ;
     RECT  0.06 20.616 0.353 20.688 ;
     RECT  0.084 20.688 0.353 20.712 ;
     RECT  0.06 20.712 0.353 20.784 ;
     RECT  0.084 20.784 0.353 20.808 ;
     RECT  0.06 20.808 0.353 20.88 ;
     RECT  0.084 20.88 0.353 20.904 ;
     RECT  0.06 20.904 0.353 20.976 ;
     RECT  0.084 20.976 0.353 21 ;
     RECT  0.06 21 0.353 21.072 ;
     RECT  0.084 21.072 0.353 21.096 ;
     RECT  0.06 21.096 0.353 21.168 ;
     RECT  0.084 21.168 0.353 21.192 ;
     RECT  0.06 21.192 0.353 21.264 ;
     RECT  0.084 21.264 0.353 21.288 ;
     RECT  0.06 21.288 0.353 21.36 ;
     RECT  0.084 21.36 0.353 21.384 ;
     RECT  0.06 21.384 0.353 21.456 ;
     RECT  0.084 21.456 0.353 21.48 ;
     RECT  0.06 21.48 0.353 21.552 ;
     RECT  0.084 21.552 0.353 21.576 ;
     RECT  0.06 21.576 0.353 21.648 ;
     RECT  0.084 21.648 0.353 21.672 ;
     RECT  0.06 21.672 0.353 21.744 ;
     RECT  0.084 21.744 0.353 21.768 ;
     RECT  0.06 21.768 0.353 21.84 ;
     RECT  0.084 21.84 0.353 21.864 ;
     RECT  0.06 21.864 0.353 21.936 ;
     RECT  0.084 21.936 0.353 21.96 ;
     RECT  0.06 21.96 0.353 22.032 ;
     RECT  0.084 22.032 0.353 22.056 ;
     RECT  0.06 22.056 0.353 22.128 ;
     RECT  0.084 22.128 0.353 22.152 ;
     RECT  0.06 22.152 0.353 22.224 ;
     RECT  0.084 22.224 0.353 22.248 ;
     RECT  0.06 22.248 0.353 22.32 ;
     RECT  0.084 22.32 0.353 22.344 ;
     RECT  0.06 22.344 0.353 22.416 ;
     RECT  0.084 22.416 0.353 22.44 ;
     RECT  0.06 22.44 0.353 22.512 ;
     RECT  0.084 22.512 0.353 22.536 ;
     RECT  0.06 22.536 0.353 22.608 ;
     RECT  0.084 22.608 0.353 22.632 ;
     RECT  0.06 22.632 0.353 22.704 ;
     RECT  0.084 22.704 0.353 22.728 ;
     RECT  0.06 22.728 0.353 22.8 ;
     RECT  0.084 22.8 0.353 22.824 ;
     RECT  0.06 22.824 0.353 22.896 ;
     RECT  0.084 22.896 0.353 22.92 ;
     RECT  0.06 22.92 0.353 22.992 ;
     RECT  0.084 22.992 0.353 23.016 ;
     RECT  0.06 23.016 0.353 23.088 ;
     RECT  0.084 23.088 0.353 23.112 ;
     RECT  0.06 23.112 0.353 23.184 ;
     RECT  0.084 23.184 0.353 23.208 ;
     RECT  0.06 23.208 0.353 23.28 ;
     RECT  0.084 23.28 0.353 23.304 ;
     RECT  0.06 23.304 0.353 23.376 ;
     RECT  0.084 23.376 0.353 23.4 ;
     RECT  0.06 23.4 0.353 23.472 ;
     RECT  0.084 23.472 0.353 23.496 ;
     RECT  0.06 23.496 0.353 23.568 ;
     RECT  0.084 23.568 0.353 23.592 ;
     RECT  0.06 23.592 0.353 23.664 ;
     RECT  0.084 23.664 0.353 23.688 ;
     RECT  0.06 23.688 0.353 23.76 ;
     RECT  0.084 23.76 0.353 23.784 ;
     RECT  0.06 23.784 0.353 23.856 ;
     RECT  0.084 23.856 0.353 23.88 ;
     RECT  0.06 23.88 0.353 23.952 ;
     RECT  0.084 23.952 0.353 23.976 ;
     RECT  0.06 23.976 0.353 24.048 ;
     RECT  0.084 24.048 0.353 24.072 ;
     RECT  0.06 24.072 0.353 24.144 ;
     RECT  0.084 24.144 0.353 24.168 ;
     RECT  0.06 24.168 0.353 24.24 ;
     RECT  0.084 24.24 0.353 24.264 ;
     RECT  0.06 24.264 0.353 24.336 ;
     RECT  0.084 24.336 0.353 24.36 ;
     RECT  0.06 24.36 0.353 24.432 ;
     RECT  0.084 24.432 0.353 24.456 ;
     RECT  0.06 24.456 0.353 24.528 ;
     RECT  0.084 24.528 0.353 24.552 ;
     RECT  0.06 24.552 0.353 24.624 ;
     RECT  0.084 24.624 0.353 24.648 ;
     RECT  0.06 24.648 0.353 24.72 ;
     RECT  0.084 24.72 0.353 24.744 ;
     RECT  0.06 24.744 0.353 24.816 ;
     RECT  0.084 24.816 0.353 24.84 ;
     RECT  0.06 24.84 0.353 24.912 ;
     RECT  0.084 24.912 0.353 24.936 ;
     RECT  0.06 24.936 0.353 25.008 ;
     RECT  0.084 25.008 0.353 25.032 ;
     RECT  0.06 25.032 0.353 25.104 ;
     RECT  0.084 25.104 0.353 25.128 ;
     RECT  0.06 25.128 0.353 25.2 ;
     RECT  0.084 25.2 0.353 25.224 ;
     RECT  0.06 25.224 0.353 25.296 ;
     RECT  0.084 25.296 0.353 25.32 ;
     RECT  0.06 25.32 0.353 25.392 ;
     RECT  0.084 25.392 0.353 25.416 ;
     RECT  0.06 25.416 0.353 25.488 ;
     RECT  0.084 25.488 0.353 25.512 ;
     RECT  0.353 13.296 0.533 25.416 ;
     RECT  0.533 13.296 0.569 25.32 ;
     RECT  0.084 27.696 0.569 27.72 ;
     RECT  0.06 27.72 0.569 27.792 ;
     RECT  0.084 27.792 0.569 27.816 ;
     RECT  0.06 27.816 0.569 27.888 ;
     RECT  0.084 27.888 0.569 27.912 ;
     RECT  0.06 27.912 0.569 27.984 ;
     RECT  0.084 27.984 0.569 28.008 ;
     RECT  0.06 28.008 0.569 28.08 ;
     RECT  0.084 28.08 0.569 28.104 ;
     RECT  0.06 28.104 0.569 28.176 ;
     RECT  0.084 28.176 0.569 28.2 ;
     RECT  0.06 28.2 0.569 28.272 ;
     RECT  0.084 28.272 0.569 28.296 ;
     RECT  0.06 28.296 0.569 28.368 ;
     RECT  0.084 28.368 0.569 28.392 ;
     RECT  0.06 28.392 0.569 28.464 ;
     RECT  0.084 28.464 0.569 28.488 ;
     RECT  0.06 28.488 0.569 28.56 ;
     RECT  0.084 28.56 0.569 28.584 ;
     RECT  0.569 13.296 0.605 25.032 ;
     RECT  0.181 6.048 2.408 6.648 ;
     RECT  0.229 8.16 2.408 8.184 ;
     RECT  0.605 13.296 2.408 23.352 ;
     RECT  0.605 24.336 2.408 25.032 ;
     RECT  0.569 27.888 2.408 28.584 ;
     RECT  2.408 2.148 2.512 30.252 ;
     RECT  2.512 2.418 2.704 29.982 ;
     RECT  2.704 6.048 2.801 8.184 ;
     RECT  2.801 6.144 5.108 8.184 ;
     RECT  2.704 11.184 5.108 11.208 ;
     RECT  2.704 13.296 5.108 23.352 ;
     RECT  2.704 24.336 5.108 25.032 ;
     RECT  2.704 27.888 5.108 28.968 ;
     RECT  5.108 2.148 5.212 30.252 ;
     RECT  5.212 2.418 5.404 29.982 ;
     RECT  5.404 11.184 6.721 11.208 ;
     RECT  5.404 13.344 6.829 23.352 ;
     RECT  5.404 24.336 6.829 25.032 ;
     RECT  5.404 6.144 7.808 8.184 ;
     RECT  6.721 11.184 7.808 11.304 ;
     RECT  6.829 13.344 7.808 25.032 ;
     RECT  5.404 27.888 7.808 28.968 ;
     RECT  7.808 2.148 7.912 30.252 ;
     RECT  7.912 2.418 8.104 29.982 ;
     RECT  8.104 6.144 10.508 8.184 ;
     RECT  8.104 11.184 10.508 11.208 ;
     RECT  8.104 13.584 10.508 16.344 ;
     RECT  8.104 17.424 10.508 25.032 ;
     RECT  8.104 27.888 10.508 28.968 ;
     RECT  10.508 2.148 10.612 30.252 ;
     RECT  10.612 2.418 10.804 29.982 ;
     RECT  10.804 13.584 10.829 25.032 ;
     RECT  10.829 13.584 10.973 23.352 ;
     RECT  10.973 14.448 11.513 23.352 ;
     RECT  11.513 14.736 11.549 23.352 ;
     RECT  11.549 14.736 11.693 17.112 ;
     RECT  11.549 18.096 11.891 23.352 ;
     RECT  11.891 18.192 11.981 23.352 ;
     RECT  10.804 11.28 12.121 11.304 ;
     RECT  12.121 10.848 12.301 11.304 ;
     RECT  12.049 12.528 12.301 12.552 ;
     RECT  12.301 10.848 12.517 12.552 ;
     RECT  12.517 10.848 12.949 12.792 ;
     RECT  11.693 15.216 12.949 17.112 ;
     RECT  10.804 6.144 12.985 8.184 ;
     RECT  12.949 10.32 13.093 12.792 ;
     RECT  12.985 6.144 13.208 8.568 ;
     RECT  13.093 10.32 13.208 13.272 ;
     RECT  12.949 14.448 13.208 17.112 ;
     RECT  11.981 18.72 13.208 23.352 ;
     RECT  10.829 24.336 13.208 25.032 ;
     RECT  13.093 26.64 13.208 26.664 ;
     RECT  10.804 27.888 13.208 28.968 ;
     RECT  13.208 2.148 13.312 30.252 ;
     RECT  13.312 2.418 13.504 29.982 ;
     RECT  13.504 26.64 13.619 26.664 ;
     RECT  13.504 6.144 13.745 13.176 ;
     RECT  13.745 6.144 13.853 13.08 ;
     RECT  13.504 14.208 13.907 23.352 ;
     RECT  13.504 27.888 14.429 27.912 ;
     RECT  13.853 6.144 14.501 12.552 ;
     RECT  13.907 14.208 14.924 16.92 ;
     RECT  13.907 17.904 14.924 23.352 ;
     RECT  14.501 6.144 14.933 11.976 ;
     RECT  15.397 13.056 15.541 13.08 ;
     RECT  14.924 14.208 15.541 23.352 ;
     RECT  14.933 11.184 15.865 11.976 ;
     RECT  15.541 13.056 15.865 23.352 ;
     RECT  14.933 6.144 15.908 10.104 ;
     RECT  15.865 11.184 15.908 23.352 ;
     RECT  13.504 24.432 15.908 25.032 ;
     RECT  15.908 2.148 16.012 30.252 ;
     RECT  16.012 2.418 16.204 29.982 ;
     RECT  16.204 24.432 16.409 24.936 ;
     RECT  16.204 6.624 16.769 22.008 ;
     RECT  16.204 23.328 16.805 23.352 ;
     RECT  16.409 24.432 17.165 24.456 ;
     RECT  16.769 6.672 17.237 22.008 ;
     RECT  17.237 8.928 17.309 22.008 ;
     RECT  17.309 18.144 17.345 22.008 ;
     RECT  17.309 8.928 17.417 17.16 ;
     RECT  17.345 18.144 17.561 21.24 ;
     RECT  17.237 7.2 18.608 7.416 ;
     RECT  17.417 8.928 18.608 9.288 ;
     RECT  17.417 10.56 18.608 17.16 ;
     RECT  17.561 18.144 18.608 20.712 ;
     RECT  18.608 2.148 18.712 30.252 ;
     RECT  18.712 2.418 18.904 29.982 ;
     RECT  18.904 6.864 19.897 20.712 ;
     RECT  19.897 6.864 21.516 6.888 ;
     RECT  19.897 6.888 21.564 6.96 ;
     RECT  19.897 6.96 21.516 6.984 ;
     RECT  19.897 6.984 21.564 7.056 ;
     RECT  19.897 7.056 21.516 7.08 ;
     RECT  19.897 7.08 21.564 7.152 ;
     RECT  19.897 7.152 21.516 7.176 ;
     RECT  19.897 7.176 21.564 7.248 ;
     RECT  19.897 7.248 21.516 7.272 ;
     RECT  19.897 7.272 21.564 7.344 ;
     RECT  19.897 7.344 21.516 7.368 ;
     RECT  19.897 7.368 21.564 7.44 ;
     RECT  19.897 7.44 21.516 7.464 ;
     RECT  19.897 7.464 21.564 7.536 ;
     RECT  19.897 7.536 21.516 7.56 ;
     RECT  19.897 7.56 21.564 7.632 ;
     RECT  19.897 7.632 21.516 7.656 ;
     RECT  19.897 7.656 21.564 7.728 ;
     RECT  19.897 7.728 21.516 7.752 ;
     RECT  19.897 7.752 21.564 7.824 ;
     RECT  19.897 7.824 21.516 7.848 ;
     RECT  19.897 7.848 21.564 7.92 ;
     RECT  19.897 7.92 21.516 7.944 ;
     RECT  19.897 7.944 21.564 8.016 ;
     RECT  19.897 8.016 21.516 8.04 ;
     RECT  19.897 8.04 21.564 8.112 ;
     RECT  19.897 8.112 21.516 8.136 ;
     RECT  19.897 8.136 21.564 8.208 ;
     RECT  19.897 8.208 21.516 8.232 ;
     RECT  19.897 8.232 21.564 8.304 ;
     RECT  19.897 8.304 21.516 8.328 ;
     RECT  19.897 8.328 21.564 8.4 ;
     RECT  19.897 8.4 21.516 8.424 ;
     RECT  19.897 8.424 21.564 8.496 ;
     RECT  19.897 8.496 21.516 8.52 ;
     RECT  19.897 8.52 21.564 8.592 ;
     RECT  19.897 8.592 21.516 8.616 ;
     RECT  19.897 8.616 21.564 8.688 ;
     RECT  19.897 8.688 21.516 8.712 ;
     RECT  19.897 8.712 21.564 8.784 ;
     RECT  19.897 8.784 21.516 8.808 ;
     RECT  19.897 8.808 21.564 8.88 ;
     RECT  19.897 8.88 21.516 8.904 ;
     RECT  19.897 8.904 21.564 8.976 ;
     RECT  19.897 8.976 21.516 9 ;
     RECT  19.897 9 21.564 9.072 ;
     RECT  19.897 9.072 21.516 9.096 ;
     RECT  19.897 9.096 21.564 9.168 ;
     RECT  19.897 9.168 21.516 9.192 ;
     RECT  19.897 9.192 21.564 9.264 ;
     RECT  19.897 9.264 21.516 9.288 ;
     RECT  19.897 9.288 21.564 9.36 ;
     RECT  19.897 9.36 21.516 9.384 ;
     RECT  19.897 9.384 21.564 9.456 ;
     RECT  19.897 9.456 21.516 9.48 ;
     RECT  19.897 9.48 21.564 9.552 ;
     RECT  19.897 9.552 21.516 9.576 ;
     RECT  19.897 9.576 21.564 9.648 ;
     RECT  19.897 9.648 21.516 9.672 ;
     RECT  19.897 9.672 21.564 9.744 ;
     RECT  19.897 9.744 21.516 9.768 ;
     RECT  19.897 9.768 21.564 9.84 ;
     RECT  19.897 9.84 21.516 9.864 ;
     RECT  19.897 9.864 21.564 9.936 ;
     RECT  19.897 9.936 21.516 9.96 ;
     RECT  19.897 9.96 21.564 10.032 ;
     RECT  19.897 10.032 21.516 10.056 ;
     RECT  19.897 10.056 21.564 10.128 ;
     RECT  19.897 10.128 21.516 10.152 ;
     RECT  19.897 10.152 21.564 10.224 ;
     RECT  19.897 10.224 21.516 10.248 ;
     RECT  19.897 10.248 21.564 10.32 ;
     RECT  19.897 10.32 21.516 10.344 ;
     RECT  19.897 10.344 21.564 10.416 ;
     RECT  19.897 10.416 21.516 10.44 ;
     RECT  19.897 10.44 21.564 10.512 ;
     RECT  19.897 10.512 21.516 10.536 ;
     RECT  19.897 10.536 21.564 10.608 ;
     RECT  19.897 10.608 21.516 10.632 ;
     RECT  19.897 10.632 21.564 10.704 ;
     RECT  19.897 10.704 21.516 10.728 ;
     RECT  19.897 10.728 21.564 10.8 ;
     RECT  19.897 10.8 21.516 10.824 ;
     RECT  19.897 10.824 21.564 10.896 ;
     RECT  19.897 10.896 21.516 10.92 ;
     RECT  19.897 10.92 21.564 10.992 ;
     RECT  19.897 10.992 21.516 11.016 ;
     RECT  19.897 11.016 21.564 11.088 ;
     RECT  19.897 11.088 21.516 11.112 ;
     RECT  19.897 11.112 21.564 11.184 ;
     RECT  19.897 11.184 21.516 11.208 ;
     RECT  19.897 11.208 21.564 11.28 ;
     RECT  19.897 11.28 21.516 11.304 ;
     RECT  19.897 11.304 21.564 11.376 ;
     RECT  19.897 11.376 21.516 11.4 ;
     RECT  19.897 11.4 21.564 11.472 ;
     RECT  19.897 11.472 21.516 11.496 ;
     RECT  19.897 11.496 21.564 11.568 ;
     RECT  19.897 11.568 21.516 11.592 ;
     RECT  19.897 11.592 21.564 11.664 ;
     RECT  19.897 11.664 21.516 11.688 ;
     RECT  19.897 11.688 21.564 11.76 ;
     RECT  19.897 11.76 21.516 11.784 ;
     RECT  19.897 11.784 21.564 11.856 ;
     RECT  19.897 11.856 21.516 11.88 ;
     RECT  19.897 11.88 21.564 11.952 ;
     RECT  19.897 11.952 21.516 11.976 ;
     RECT  19.897 11.976 21.564 12.048 ;
     RECT  19.897 12.048 21.516 12.072 ;
     RECT  19.897 12.072 21.564 12.144 ;
     RECT  19.897 12.144 21.516 12.168 ;
     RECT  19.897 12.168 21.564 12.24 ;
     RECT  19.897 12.24 21.516 12.264 ;
     RECT  19.897 12.264 21.564 12.336 ;
     RECT  19.897 12.336 21.516 12.36 ;
     RECT  19.897 12.36 21.564 12.432 ;
     RECT  19.897 12.432 21.516 12.456 ;
     RECT  19.897 12.456 21.564 12.528 ;
     RECT  19.897 12.528 21.516 12.552 ;
     RECT  19.897 12.552 21.564 12.624 ;
     RECT  19.897 12.624 21.516 12.648 ;
     RECT  19.897 12.648 21.564 12.72 ;
     RECT  19.897 12.72 21.516 12.744 ;
     RECT  19.897 12.744 21.564 12.816 ;
     RECT  19.897 12.816 21.516 12.84 ;
     RECT  19.897 12.84 21.564 12.912 ;
     RECT  19.897 12.912 21.516 12.936 ;
     RECT  19.897 12.936 21.564 13.008 ;
     RECT  19.897 13.008 21.516 13.032 ;
     RECT  19.897 13.032 21.564 13.104 ;
     RECT  19.897 13.104 21.516 13.128 ;
     RECT  19.897 13.128 21.564 13.2 ;
     RECT  19.897 13.2 21.516 13.224 ;
     RECT  19.897 13.224 21.564 13.296 ;
     RECT  19.897 13.296 21.516 13.32 ;
     RECT  19.897 13.32 21.564 13.392 ;
     RECT  19.897 13.392 21.516 13.416 ;
     RECT  19.897 13.416 21.564 13.488 ;
     RECT  19.897 13.488 21.516 13.512 ;
     RECT  19.897 13.512 21.564 13.584 ;
     RECT  19.897 13.584 21.516 13.608 ;
     RECT  19.897 13.608 21.564 13.68 ;
     RECT  19.897 13.68 21.516 13.704 ;
     RECT  19.897 13.704 21.564 13.776 ;
     RECT  19.897 13.776 21.516 13.8 ;
     RECT  19.897 13.8 21.564 13.872 ;
     RECT  19.897 13.872 21.516 13.896 ;
     RECT  19.897 13.896 21.564 13.968 ;
     RECT  19.897 13.968 21.516 13.992 ;
     RECT  19.897 13.992 21.564 14.064 ;
     RECT  19.897 14.064 21.516 14.088 ;
     RECT  19.897 14.088 21.564 14.16 ;
     RECT  19.897 14.16 21.516 14.184 ;
     RECT  19.897 14.184 21.564 14.256 ;
     RECT  19.897 14.256 21.516 14.28 ;
     RECT  19.897 14.28 21.564 14.352 ;
     RECT  19.897 14.352 21.516 14.376 ;
     RECT  19.897 14.376 21.564 14.448 ;
     RECT  19.897 14.448 21.516 14.472 ;
     RECT  19.897 14.472 21.564 14.544 ;
     RECT  19.897 14.544 21.516 14.568 ;
     RECT  19.897 14.568 21.564 14.64 ;
     RECT  19.897 14.64 21.516 14.664 ;
     RECT  19.897 14.664 21.564 14.736 ;
     RECT  19.897 14.736 21.516 14.76 ;
     RECT  19.897 14.76 21.564 14.832 ;
     RECT  19.897 14.832 21.516 14.856 ;
     RECT  19.897 14.856 21.564 14.928 ;
     RECT  19.897 14.928 21.516 14.952 ;
     RECT  19.897 14.952 21.564 15.024 ;
     RECT  19.897 15.024 21.516 15.048 ;
     RECT  19.897 15.048 21.564 15.12 ;
     RECT  19.897 15.12 21.516 15.144 ;
     RECT  19.897 15.144 21.564 15.216 ;
     RECT  19.897 15.216 21.516 15.24 ;
     RECT  19.897 15.24 21.564 15.312 ;
     RECT  19.897 15.312 21.516 15.336 ;
     RECT  19.897 15.336 21.564 15.408 ;
     RECT  19.897 15.408 21.516 15.432 ;
     RECT  19.897 15.432 21.564 15.504 ;
     RECT  19.897 15.504 21.516 15.528 ;
     RECT  19.897 15.528 21.564 15.6 ;
     RECT  19.897 15.6 21.516 15.624 ;
     RECT  19.897 15.624 21.564 15.696 ;
     RECT  19.897 15.696 21.516 15.72 ;
     RECT  19.897 15.72 21.564 15.792 ;
     RECT  19.897 15.792 21.516 15.816 ;
     RECT  19.897 15.816 21.564 15.888 ;
     RECT  19.897 15.888 21.516 15.912 ;
     RECT  19.897 15.912 21.564 15.984 ;
     RECT  19.897 15.984 21.516 16.008 ;
     RECT  19.897 16.008 21.564 16.08 ;
     RECT  19.897 16.08 21.516 16.104 ;
     RECT  19.897 16.104 21.564 16.176 ;
     RECT  19.897 16.176 21.516 16.2 ;
     RECT  19.897 16.2 21.564 16.272 ;
     RECT  19.897 16.272 21.516 16.296 ;
     RECT  19.897 16.296 21.564 16.368 ;
     RECT  19.897 16.368 21.516 16.392 ;
     RECT  19.897 16.392 21.564 16.464 ;
     RECT  19.897 16.464 21.516 16.488 ;
     RECT  19.897 16.488 21.564 16.56 ;
     RECT  19.897 16.56 21.516 16.584 ;
     RECT  19.897 16.584 21.564 16.656 ;
     RECT  19.897 16.656 21.516 16.68 ;
     RECT  19.897 16.68 21.564 16.752 ;
     RECT  19.897 16.752 21.516 16.776 ;
     RECT  19.897 16.776 21.564 16.848 ;
     RECT  19.897 16.848 21.516 16.872 ;
     RECT  19.897 16.872 21.564 16.944 ;
     RECT  19.897 16.944 21.516 16.968 ;
     RECT  19.897 16.968 21.564 17.04 ;
     RECT  19.897 17.04 21.516 17.064 ;
     RECT  19.897 17.064 21.564 17.136 ;
     RECT  19.897 17.136 21.516 17.16 ;
     RECT  19.897 17.16 21.564 17.232 ;
     RECT  19.897 17.232 21.516 17.256 ;
     RECT  19.897 17.256 21.564 17.328 ;
     RECT  19.897 17.328 21.516 17.352 ;
     RECT  19.897 17.352 21.564 17.424 ;
     RECT  19.897 17.424 21.516 17.448 ;
     RECT  19.897 17.448 21.564 17.52 ;
     RECT  19.897 17.52 21.516 17.544 ;
     RECT  19.897 17.544 21.564 17.616 ;
     RECT  19.897 17.616 21.516 17.64 ;
     RECT  19.897 17.64 21.564 17.712 ;
     RECT  19.897 17.712 21.516 17.736 ;
     RECT  19.897 17.736 21.564 17.808 ;
     RECT  19.897 17.808 21.516 17.832 ;
     RECT  19.897 17.832 21.564 17.904 ;
     RECT  19.897 17.904 21.516 17.928 ;
     RECT  19.897 17.928 21.564 18 ;
     RECT  19.897 18 21.516 18.024 ;
     RECT  19.897 18.024 21.564 18.096 ;
     RECT  19.897 18.096 21.516 18.12 ;
     RECT  19.897 18.12 21.564 18.192 ;
     RECT  19.897 18.192 21.516 18.216 ;
     RECT  19.897 18.216 21.564 18.288 ;
     RECT  19.897 18.288 21.516 18.312 ;
     RECT  19.897 18.312 21.564 18.384 ;
     RECT  19.897 18.384 21.516 18.408 ;
     RECT  19.897 18.408 21.564 18.48 ;
     RECT  19.897 18.48 21.516 18.504 ;
     RECT  19.897 18.504 21.564 18.576 ;
     RECT  19.897 18.576 21.516 18.6 ;
     RECT  19.897 18.6 21.564 18.672 ;
     RECT  19.897 18.672 21.516 18.696 ;
     RECT  19.897 18.696 21.564 18.768 ;
     RECT  19.897 18.768 21.516 18.792 ;
     RECT  19.897 18.792 21.564 18.864 ;
     RECT  19.897 18.864 21.516 18.888 ;
     RECT  19.897 18.888 21.564 18.96 ;
     RECT  19.897 18.96 21.516 18.984 ;
     RECT  19.897 18.984 21.564 19.056 ;
     RECT  19.897 19.056 21.516 19.08 ;
     RECT  19.897 19.08 21.564 19.92 ;
     RECT  19.897 19.92 21.516 19.944 ;
     RECT  19.897 19.944 21.564 20.016 ;
     RECT  19.897 20.016 21.516 20.04 ;
     RECT  19.897 20.04 21.564 20.112 ;
     RECT  19.897 20.112 21.516 20.136 ;
     RECT  19.897 20.136 21.564 20.208 ;
     RECT  19.897 20.208 21.516 20.232 ;
     RECT  19.897 20.232 21.564 20.304 ;
     RECT  19.897 20.304 21.516 20.328 ;
     RECT  19.897 20.328 21.564 20.4 ;
     RECT  19.897 20.4 21.516 20.424 ;
     RECT  19.897 20.424 21.564 20.496 ;
     RECT  19.897 20.496 21.516 20.52 ;
     RECT  19.897 20.52 21.564 20.592 ;
     RECT  19.897 20.592 21.516 20.616 ;
     RECT  19.897 20.616 21.564 20.688 ;
     RECT  19.897 20.688 21.516 20.712 ;
     RECT  19.897 20.712 21.564 20.784 ;
     RECT  19.897 20.784 21.516 20.808 ;
    LAYER M5 ;
     RECT  2.4 2.137 2.52 2.151 ;
     RECT  5.1 2.137 5.22 2.151 ;
     RECT  7.8 2.137 7.92 2.151 ;
     RECT  10.5 2.137 10.62 2.151 ;
     RECT  13.2 2.137 13.32 2.151 ;
     RECT  15.9 2.137 16.02 2.151 ;
     RECT  18.6 2.137 18.72 2.151 ;
     RECT  0.144 6.037 0.168 6.613 ;
     RECT  15.9 2.151 16.212 6.661 ;
     RECT  13.2 2.151 13.512 7.333 ;
     RECT  15.9 6.661 17.16 7.381 ;
     RECT  18.6 2.151 18.912 7.381 ;
     RECT  15.9 7.381 18.912 7.765 ;
     RECT  14.832 7.765 18.912 8.003 ;
     RECT  0.144 6.613 0.216 8.149 ;
     RECT  17.712 8.003 18.912 8.963 ;
     RECT  14.832 8.003 16.212 9.059 ;
     RECT  13.2 7.333 13.656 9.349 ;
     RECT  14.832 9.059 14.856 9.349 ;
     RECT  13.2 9.349 14.856 9.395 ;
     RECT  13.2 9.395 14.664 11.221 ;
     RECT  15.9 9.059 16.212 11.413 ;
     RECT  13.056 11.221 14.664 11.459 ;
     RECT  14.64 11.459 14.664 11.507 ;
     RECT  13.056 11.459 13.656 11.941 ;
     RECT  12.528 11.941 13.656 12.803 ;
     RECT  15.9 11.413 16.776 12.995 ;
     RECT  15.9 12.995 16.212 13.045 ;
     RECT  13.056 12.803 13.656 13.187 ;
     RECT  15.408 13.045 16.212 14.197 ;
     RECT  13.056 13.187 13.512 14.773 ;
     RECT  0.144 8.149 0.264 16.787 ;
     RECT  15.408 14.197 16.344 16.885 ;
     RECT  0.24 16.787 0.264 17.075 ;
     RECT  13.056 14.773 13.8 17.461 ;
     RECT  15.408 16.885 17.016 17.461 ;
     RECT  14.976 17.461 17.016 17.891 ;
     RECT  14.976 17.891 16.212 17.939 ;
     RECT  13.056 17.461 13.896 18.757 ;
     RECT  10.5 2.151 10.812 19.141 ;
     RECT  11.856 18.085 11.88 19.141 ;
     RECT  10.5 19.141 11.88 19.187 ;
     RECT  15.9 17.939 16.212 19.237 ;
     RECT  13.056 18.757 14.232 19.523 ;
     RECT  0.144 20.149 0.168 20.339 ;
     RECT  15.264 19.237 16.212 20.579 ;
     RECT  17.52 18.853 17.544 20.915 ;
     RECT  13.056 19.523 14.04 21.155 ;
     RECT  10.5 19.187 11.544 22.835 ;
     RECT  13.056 21.155 13.608 26.675 ;
     RECT  13.056 26.675 13.512 28.451 ;
     RECT  13.104 28.451 13.512 28.979 ;
     RECT  2.4 2.151 2.712 30.249 ;
     RECT  5.1 2.151 5.412 30.249 ;
     RECT  7.8 2.151 8.112 30.249 ;
     RECT  10.5 22.835 10.812 30.249 ;
     RECT  13.2 28.979 13.512 30.249 ;
     RECT  15.9 20.579 16.212 30.249 ;
     RECT  18.6 8.963 18.912 30.249 ;
     RECT  2.4 30.249 2.52 30.263 ;
     RECT  5.1 30.249 5.22 30.263 ;
     RECT  7.8 30.249 7.92 30.263 ;
     RECT  10.5 30.249 10.62 30.263 ;
     RECT  13.2 30.249 13.32 30.263 ;
     RECT  15.9 30.249 16.02 30.263 ;
     RECT  18.6 30.249 18.72 30.263 ;
     RECT  17.16 6.661 18.6 7.381 ;
     RECT  13.656 7.765 14.832 9.349 ;
     RECT  16.212 8.003 17.712 8.963 ;
     RECT  14.856 9.059 15.9 9.395 ;
     RECT  14.664 9.395 15.9 11.507 ;
     RECT  13.656 11.459 14.64 11.507 ;
     RECT  16.212 12.995 16.344 14.197 ;
     RECT  13.896 17.461 14.976 17.939 ;
     RECT  16.212 17.891 17.016 18.853 ;
     RECT  13.896 17.939 15.9 18.757 ;
     RECT  10.812 18.085 11.856 19.141 ;
     RECT  11.88 18.085 13.056 19.187 ;
     RECT  14.232 18.757 15.9 19.237 ;
     RECT  16.212 18.853 17.52 20.915 ;
     RECT  17.544 18.853 18.6 20.915 ;
     RECT  11.544 19.187 13.056 22.835 ;
     RECT  14.232 19.237 15.264 19.523 ;
     RECT  14.04 19.523 15.264 20.579 ;
  END
END hbfd_lh0_136_EW
END LIBRARY
